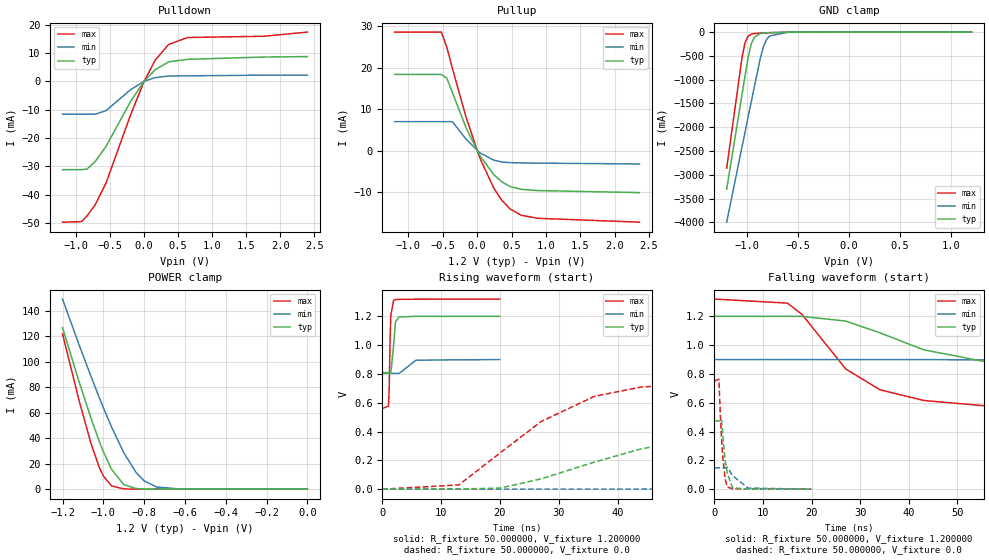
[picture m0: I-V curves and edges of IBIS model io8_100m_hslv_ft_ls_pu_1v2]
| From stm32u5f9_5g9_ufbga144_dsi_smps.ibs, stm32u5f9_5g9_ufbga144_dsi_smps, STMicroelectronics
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|   Model io8_100m_hslv_ft_ls_pu_1v2
[Model]  io8_100m_hslv_ft_ls_pu_1v2
Model_type I/O
Polarity   Non-Inverting
Enable   Active-Low
Vinl =   0.360000V
Vinh =   0.840000V
Vmeas =  0.600000V
Cref =   50.000000pF
Rref =   100.000000M
Vref =   0.0V
C_comp   3.030000pF   2.960800pF   3.078200pF
[Temperature Range]   25.000000   0.140000k   -40.000000
[Pullup Reference]   1.200000V   0.900000V   1.320000V
[Pulldown Reference]   0.0V   0.0V   0.0V
[POWER Clamp Reference]   1.200000V   0.900000V   1.320000V
[GND Clamp Reference]   0.0V   0.0V   0.0V
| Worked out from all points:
|   slope of the pulldown table from 0 to 0.18 V, typ, clamps not added: 40.7 ohm
|   slope of the pullup table from 0 to 0.18 V, typ, clamps not added: 39.5 ohm
|   GND clamp passes 1 mA (typ) near -0.51 V on its own axis
|   POWER clamp passes 1 mA (typ) near -0.86 V on its own axis
|   rising waveform, R_fixture 50.000000, V_fixture 1.200000: 20-80 % time 345ps typ, 818ps min, 225ps max; typ from 0.809 V to 1.2 V
|   rising waveform, R_fixture 50.000000, V_fixture 0.0: 20-80 % time 28.3ns typ, 68.3ns min, 16ns max; typ from 0.001 V to 0.474 V
|   falling waveform, R_fixture 50.000000, V_fixture 1.200000: 20-80 % time 23.6ns typ, 56.9ns min, 13.4ns max; typ from 1.2 V to 0.809 V
|   falling waveform, R_fixture 50.000000, V_fixture 0.0: 20-80 % time 1.04ns typ, 1.96ns min, 794ps max; typ from 0.474 V to 0.001 V
[Pulldown]
|Voltage   I(typ)   I(min)   I(max)
-1.2V     -31.16mA   -11.61mA   -49.71mA
-920mV    -31.16mA   -11.61mA   -49.49mA
-840mV    -31mA      -11.61mA   -47.54mA
-720mV    -28.32mA   -11.61mA   -43.58mA
-560mV    -22.95mA   -10.36mA   -35.89mA
-200mV    -7.146mA   -2.962mA   -11.89mA
0V        0A         0A         0A
160mV     4.047mA    1.297mA    7.361mA
360mV     6.869mA    1.868mA    13mA
640mV     7.764mA    1.921mA    15.46mA
1.76V     8.563mA    2.176mA    15.9mA
2.4V      8.725mA    2.176mA    17.37mA
[Pullup]
|Voltage   I(typ)   I(min)   I(max)
-1.2V     18.39mA    7.011mA    28.61mA
-520mV    18.39mA    7.011mA    28.61mA
-440mV    17.47mA    7.011mA    24.94mA
-360mV    14.06mA    7.011mA    19.88mA
-160mV    5.494mA    2.765mA    8.045mA
40mV      -1.16mA    -507.9uA   -1.774mA
240mV     -5.73mA    -2.255mA   -8.953mA
360mV     -7.518mA   -2.714mA   -11.96mA
480mV     -8.639mA   -2.875mA   -14.04mA
640mV     -9.31mA    -2.939mA   -15.55mA
880mV     -9.601mA   -2.983mA   -16.29mA
2.36V     -10.1mA    -3.2mA     -17.23mA
[GND_clamp]
|Voltage   I(typ)   I(min)   I(max)
-1.2V     -3.305A    -3.998A    -2.862A
-1.05V    -1.316A    -2.418A    -539.3mA
-1.02V    -921mA     -2.103A    -218.8mA
-990mV    -539.5mA   -1.788A    -87.43mA
-960mV    -252.1mA   -1.474A    -44.36mA
-930mV    -110.5mA   -1.16A     -30.32mA
-870mV    -28.03mA   -549.1mA   -21.09mA
-840mV    -18.43mA   -305.6mA   -18.27mA
-810mV    -13.9mA    -159.7mA   -15.73mA
-780mV    -11.23mA   -82.35mA   -13.37mA
-600mV    -2.976mA   -4.272mA   -3.058mA
1.2V      0A         14.73nA    0A
[POWER_clamp]
|Voltage   I(typ)   I(min)   I(max)
-1.2V     127mA      149.4mA    122.2mA
-1.12V    84.98mA    114mA      70.29mA
-1.06V    55.52mA    88.42mA    35.69mA
-1.02V    37.64mA    72.04mA    17.19mA
-1V       29.52mA    64.13mA    10.33mA
-960mV    15.7mA     48.99mA    2.596mA
-900mV    3.636mA    28.77mA    207.8uA
-840mV    502.9uA    13.24mA    43.56uA
-800mV    129uA      6.535mA    43.56uA
-740mV    25.39uA    1.726mA    43.56uA
-620mV    25.22uA    82.33uA    36.06uA
0V        0A         17.33nA    0A
[Ramp]
| variable   typ   min   max
dV/dt_r  0.28386/28.26569n   88.90177m/68.25460n 0.45097/16.01528n
dV/dt_f  0.23429/23.46226n   57.78000m/56.82292n 0.45608/13.31892n
R_load = 50.000000
[Rising Waveform]
R_fixture= 50.000000
V_fixture= 1.200000
V_fixture_min= 0.900000
V_fixture_max= 1.320000
|time   V(typ)   V(min)   V(max)
0s        809.5mV    803.7mV    559.9mV
1.041ns   809.6mV    803.7mV    577.2mV
1.161ns   809.1mV    803.7mV    690.7mV
1.321ns   806.3mV    803.7mV    1.05V
1.441ns   804.1mV    803.7mV    1.209V
1.922ns   1.005V     803.7mV    1.312V
2.242ns   1.163V     803.8mV    1.317V
2.843ns   1.196V     803.5mV    1.318V
5.726ns   1.2V       896mV      1.319V
19.94ns   1.2V       900mV      1.32V
[Rising Waveform]
R_fixture= 50.000000
V_fixture= 0.0
V_fixture_min= 0.0
V_fixture_max= 0.0
|time   V(typ)   V(min)   V(max)
0s        591.7uV    600.4uV    545.2uV
13.01ns   1.408mV    841.7uV    29.79mV
20.02ns   7.847mV    853.3uV    252mV
27.03ns   72.56mV    891.2uV    470.5mV
36.04ns   188.1mV    1.048mV    644.4mV
44.04ns   280.4mV    1.23mV     709.6mV
58.06ns   384.6mV    4.151mV    743.9mV
91.09ns   463mV      46.26mV    751.9mV
193.2ns   473.7mV    140.2mV    752.1mV
498.5ns   473.8mV    148.9mV    752.2mV
[Falling Waveform]
R_fixture= 50.000000
V_fixture= 1.200000
V_fixture_min= 0.900000
V_fixture_max= 1.320000
|time   V(typ)   V(min)   V(max)
0s        1.2V       900mV      1.32V
15.02ns   1.2V       900.2mV    1.292V
18.02ns   1.2V       900.1mV    1.213V
27.03ns   1.167V     900mV      834.7mV
34.03ns   1.086V     900mV      690.9mV
43.04ns   968mV      899.9mV    616.1mV
56.06ns   883.2mV    897.7mV    578.1mV
83.08ns   826mV      868.8mV    562.2mV
166.2ns   809.6mV    812mV      559.9mV
498.5ns   809.5mV    803.7mV    559.9mV
[Falling Waveform]
R_fixture= 50.000000
V_fixture= 0.0
V_fixture_min= 0.0
V_fixture_max= 0.0
|time   V(typ)   V(min)   V(max)
0s        473.8mV    148.9mV    752.2mV
920.9ps   474.2mV    149mV      763.7mV
1.201ns   475.8mV    149mV      525.1mV
1.441ns   485.5mV    149mV      362.5mV
1.682ns   393.1mV    149.1mV    238.6mV
2.202ns   196.8mV    148.9mV    68.8mV
2.643ns   111.3mV    152.7mV    15.72mV
3.724ns   9.728mV    94.41mV    2.95mV
6.927ns   681uV      8.118mV    1.67mV
19.94ns   591.7uV    600.4uV    545.2uV
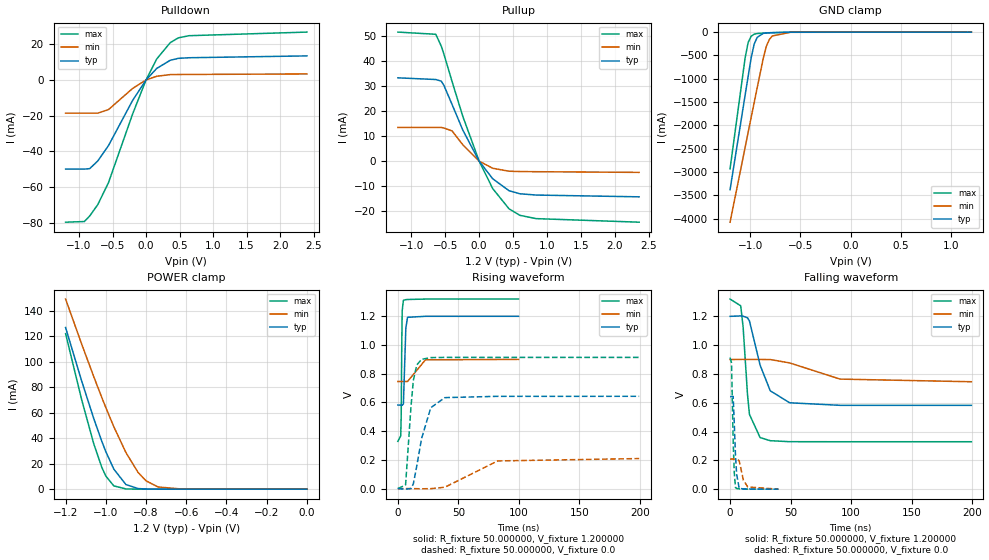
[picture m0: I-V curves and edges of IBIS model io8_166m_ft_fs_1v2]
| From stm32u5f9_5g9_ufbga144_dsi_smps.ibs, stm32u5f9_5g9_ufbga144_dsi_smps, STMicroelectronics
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|   Model io8_166m_ft_fs_1v2
[Model]  io8_166m_ft_fs_1v2
Model_type I/O
Polarity   Non-Inverting
Enable   Active-Low
Vinl =   0.360000V
Vinh =   0.840000V
Vmeas =  0.600000V
Cref =   50.000000pF
Rref =   100.000000M
Vref =   0.0V
C_comp   3.151500pF   3.086800pF   3.197700pF
[Temperature Range]   25.000000   0.140000k   -40.000000
[Pullup Reference]   1.200000V   0.900000V   1.320000V
[Pulldown Reference]   0.0V   0.0V   0.0V
[POWER Clamp Reference]   1.200000V   0.900000V   1.320000V
[GND Clamp Reference]   0.0V   0.0V   0.0V
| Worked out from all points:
|   slope of the pulldown table from 0 to 0.18 V, typ, clamps not added: 25.4 ohm
|   slope of the pullup table from 0 to 0.18 V, typ, clamps not added: 27.8 ohm
|   GND clamp passes 1 mA (typ) near -0.51 V on its own axis
|   POWER clamp passes 1 mA (typ) near -0.86 V on its own axis
|   rising waveform, R_fixture 50.000000, V_fixture 1.200000: 20-80 % time 1.12ns typ, 3.02ns min, 570ps max; typ from 0.582 V to 1.2 V
|   rising waveform, R_fixture 50.000000, V_fixture 0.0: 20-80 % time 9.52ns typ, 24.6ns min, 4.59ns max; typ from 0 V to 0.643 V
|   falling waveform, R_fixture 50.000000, V_fixture 1.200000: 20-80 % time 12ns typ, 29.2ns min, 5.06ns max; typ from 1.2 V to 0.582 V
|   falling waveform, R_fixture 50.000000, V_fixture 0.0: 20-80 % time 1.95ns typ, 3.63ns min, 1.46ns max; typ from 0.643 V to 0 V
[Pulldown]
|Voltage   I(typ)   I(min)   I(max)
-1.2V     -49.86mA   -18.57mA   -79.57mA
-920mV    -49.86mA   -18.57mA   -79.2mA
-840mV    -49.6mA    -18.57mA   -76.08mA
-720mV    -45.32mA   -18.57mA   -69.74mA
-560mV    -36.71mA   -16.58mA   -57.44mA
-200mV    -11.43mA   -4.74mA    -19.03mA
0V        0A         -500fA     0A
160mV     6.477mA    2.075mA    11.78mA
360mV     10.99mA    2.99mA     20.81mA
480mV     12.07mA    3.054mA    23.53mA
640mV     12.43mA    3.075mA    24.76mA
2.4V      13.46mA    3.37mA     26.78mA
[Pullup]
|Voltage   I(typ)   I(min)   I(max)
-1.2V     33.42mA    13.53mA    51.76mA
-640mV    32.74mA    13.53mA    50.88mA
-560mV    32.1mA     13.53mA    46.17mA
-520mV    30.37mA    13.29mA    42.92mA
-400mV    22.74mA    12.14mA    31.93mA
-240mV    12.39mA    6.508mA    17.85mA
0V        580fA      234pA      0A
200mV     -7.072mA   -2.851mA   -11mA
440mV     -11.84mA   -4.03mA    -19.1mA
600mV     -13.07mA   -4.154mA   -21.71mA
840mV     -13.59mA   -4.223mA   -23.04mA
2.36V     -14.3mA    -4.5mA     -24.47mA
[GND_clamp]
|Voltage   I(typ)   I(min)   I(max)
-1.2V     -3.379A    -4.076A    -2.932A
-1.05V    -1.35A     -2.47A     -550.7mA
-1.02V    -947.8mA   -2.149A    -221.5mA
-990mV    -552.4mA   -1.829A    -88.44mA
-960mV    -255.3mA   -1.51A     -44.87mA
-930mV    -111.8mA   -1.191A    -30.68mA
-870mV    -28.36mA   -564.6mA   -21.34mA
-840mV    -18.65mA   -309.5mA   -18.49mA
-810mV    -14.07mA   -161.6mA   -15.92mA
-780mV    -11.37mA   -83.33mA   -13.53mA
-600mV    -3.009mA   -4.322mA   -3.091mA
1.2V      0A         13.65nA    0A
[POWER_clamp]
|Voltage   I(typ)   I(min)   I(max)
-1.2V     127mA      149.4mA    122.2mA
-1.12V    84.97mA    114mA      70.27mA
-1.06V    55.51mA    88.42mA    35.67mA
-1.02V    37.63mA    72.04mA    17.17mA
-1V       29.51mA    64.13mA    10.3mA
-960mV    15.69mA    48.99mA    2.571mA
-900mV    3.624mA    28.77mA    182.8uA
-840mV    490.7uA    13.24mA    11.35uA
-800mV    116.8uA    6.532mA    1.77uA
-740mV    13.2uA     1.724mA    109.1nA
-620mV    167.4nA    79.36uA    0A
0V        0A         17.87nA    0A
[Ramp]
| variable   typ   min   max
dV/dt_r  0.38562/9.51064n   0.12548/24.55913n   0.54826/4.57912n
dV/dt_f  0.37087/11.97332n   92.44800m/29.20183n 0.59438/5.04838n
R_load = 50.000000
[Rising Waveform]
R_fixture= 50.000000
V_fixture= 1.200000
V_fixture_min= 0.900000
V_fixture_max= 1.320000
|time   V(typ)   V(min)   V(max)
0s        581.9mV    745.9mV    329.4mV
2.402ns   582mV      745.9mV    367.6mV
2.803ns   582mV      745.9mV    517.9mV
3.203ns   581.5mV    745.9mV    965.7mV
3.604ns   580.2mV    745.9mV    1.239V
4.605ns   589mV      745.9mV    1.311V
6.607ns   1.116V     745.9mV    1.316V
8.008ns   1.193V     745.9mV    1.317V
22.82ns   1.2V       896.8mV    1.32V
99.7ns    1.2V       900mV      1.32V
[Rising Waveform]
R_fixture= 50.000000
V_fixture= 0.0
V_fixture_min= 0.0
V_fixture_max= 0.0
|time   V(typ)   V(min)   V(max)
0s        1.413uV    1.121uV    1.253uV
6.406ns   -3.831mV   413nV      25.35mV
10.81ns   771.6uV    3.329uV    563.2mV
12.81ns   32.74mV    37.8uV     752.9mV
15.62ns   155.8mV    -550.3uV   860.7mV
19.62ns   348.5mV    -1.365mV   900.4mV
27.23ns   563.5mV    -221.4uV   912.3mV
38.84ns   633.6mV    9.681mV    913.7mV
82.48ns   642.7mV    192.8mV    913.7mV
199.4ns   642.8mV    209.3mV    913.8mV
[Falling Waveform]
R_fixture= 50.000000
V_fixture= 1.200000
V_fixture_min= 0.900000
V_fixture_max= 1.320000
|time   V(typ)   V(min)   V(max)
0s        1.2V       900mV      1.32V
8.809ns   1.203V     901.1mV    1.273V
10.81ns   1.201V     901.2mV    1.124V
14.41ns   1.19V      900.6mV    657.4mV
16.02ns   1.168V     900.6mV    519.4mV
24.82ns   861.1mV    900.6mV    358.2mV
33.23ns   682.9mV    900mV      336.5mV
49.25ns   599.8mV    876.6mV    329.7mV
90.89ns   582.2mV    764.2mV    329.4mV
199.4ns   581.9mV    745.9mV    329.4mV
[Falling Waveform]
R_fixture= 50.000000
V_fixture= 0.0
V_fixture_min= 0.0
V_fixture_max= 0.0
|time   V(typ)   V(min)   V(max)
0s        642.8mV    209.3mV    913.8mV
1.201ns   642.6mV    209.3mV    877.2mV
2.563ns   644mV      209.3mV    333mV
3.443ns   466.1mV    209.2mV    120.2mV
4.484ns   234.5mV    208.9mV    11.92mV
5.445ns   103.8mV    210.9mV    4.661mV
7.528ns   6.591mV    197.8mV    2.295mV
11.05ns   1.415mV    61.13mV    857.5uV
14.65ns   736.8uV    15.42mV    353.8uV
39.88ns   1.413uV    1.121uV    1.253uV
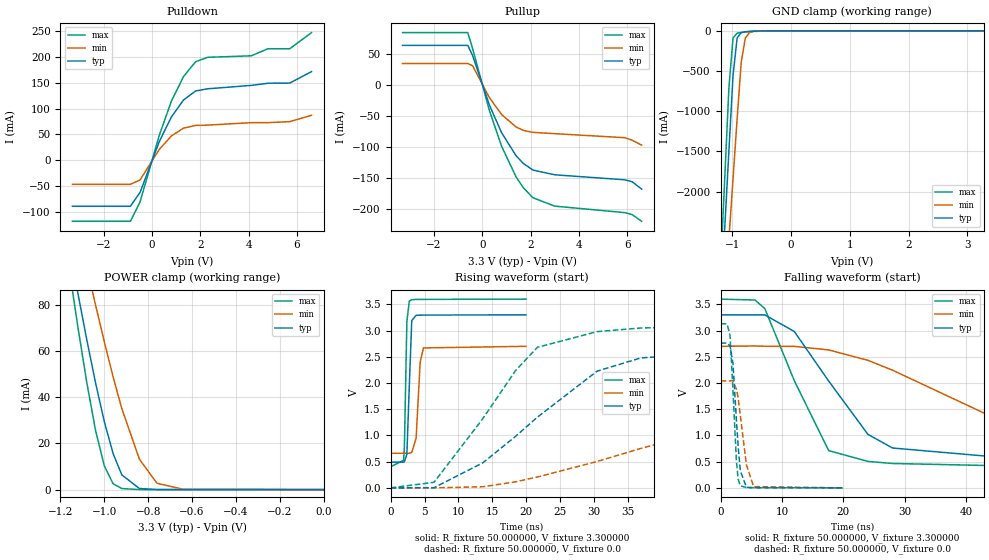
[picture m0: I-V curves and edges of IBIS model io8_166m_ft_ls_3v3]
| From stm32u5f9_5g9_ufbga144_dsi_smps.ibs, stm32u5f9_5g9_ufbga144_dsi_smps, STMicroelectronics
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|   Model io8_166m_ft_ls_3v3
[Model]  io8_166m_ft_ls_3v3
Model_type I/O
Polarity   Non-Inverting
Enable   Active-Low
Vinl =   0.990000V
Vinh =   2.310000V
Vmeas =  1.650000V
Cref =   50.000000pF
Rref =   100.000000M
Vref =   0.0V
C_comp   3.517100pF   3.489300pF   3.557700pF
[Temperature Range]   25.000000   0.140000k   -40.000000
[Pullup Reference]   3.300000V   2.700000V   3.600000V
[Pulldown Reference]   0.0V   0.0V   0.0V
[POWER Clamp Reference]   3.300000V   2.700000V   3.600000V
[GND Clamp Reference]   0.0V   0.0V   0.0V
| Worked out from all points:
|   slope of the pulldown table from 0 to 0.495 V, typ, clamps not added: 8.73 ohm
|   slope of the pullup table from 0 to 0.495 V, typ, clamps not added: 9.64 ohm
|   GND clamp passes 1 mA (typ) near -0.50 V on its own axis
|   POWER clamp passes 1 mA (typ) near -0.85 V on its own axis
|   rising waveform, R_fixture 50.000000, V_fixture 3.300000: 20-80 % time 307ps typ, 455ps min, 272ps max; typ from 0.49 V to 3.3 V
|   rising waveform, R_fixture 50.000000, V_fixture 0.0: 20-80 % time 15.8ns typ, 34.2ns min, 10.3ns max; typ from 0 V to 2.76 V
|   falling waveform, R_fixture 50.000000, V_fixture 3.300000: 20-80 % time 10.1ns typ, 22.3ns min, 6.59ns max; typ from 3.3 V to 0.49 V
|   falling waveform, R_fixture 50.000000, V_fixture 0.0: 20-80 % time 898ps typ, 1.3ns min, 736ps max; typ from 2.76 V to 0 V
[Pulldown]
|Voltage   I(typ)   I(min)   I(max)
-3.3V     -89.72mA   -47.06mA   -119mA
-900mV    -89.72mA   -47.06mA   -119mA
-500mV    -62.92mA   -38.71mA   -81.44mA
300mV     36.2mA     21.01mA    48.7mA
800mV     84.07mA    46.96mA    114.8mA
1.3V      116.7mA    62.09mA    162.4mA
1.8V      134.4mA    67.39mA    191.2mA
2.3V      138.6mA    67.98mA    199.8mA
4.1V      145.2mA    72.79mA    202.7mA
4.8V      149.4mA    72.79mA    216.5mA
5.7V      149.8mA    74.8mA     216.5mA
6.6V      172mA      87.1mA     247.9mA
[Pullup]
|Voltage   I(typ)   I(min)   I(max)
-3.3V     64.11mA    34.77mA    84.74mA
-600mV    64.11mA    34.77mA    84.74mA
-400mV    47.78mA    31.25mA    59.06mA
300mV     -32.62mA   -20.62mA   -41.63mA
800mV     -76.87mA   -47.45mA   -98.74mA
1.4V      -114.1mA   -67.68mA   -148.3mA
1.7V      -126.6mA   -73.14mA   -165.8mA
2.1V      -137.3mA   -76.42mA   -182mA
3V        -144.9mA   -78.48mA   -195.5mA
5.9V      -153mA     -85mA      -206mA
6.2V      -156mA     -89mA      -209mA
6.6V      -168mA     -97mA      -220mA
[GND_clamp]
|Voltage   I(typ)   I(min)   I(max)
-3.3V     -9.098A    -9.372A    -9.671A
-1.2V     -3.386A    -4.091A    -2.933A
-1.13V    -2.437A    -3.34A     -1.815A
-1.06V    -1.49A     -2.588A    -705.6mA
-990mV    -555.7mA   -1.839A    -89.03mA
-920mV    -88.12mA   -1.093A    -28.78mA
-850mV    -22.35mA   -387.4mA   -19.84mA
-780mV    -12.12mA   -88.01mA   -13.88mA
-710mV    -7.71mA    -22.52mA   -8.846mA
-640mV    -4.545mA   -7.864mA   -4.87mA
-360mV    -31.12uA   -173.5uA   -8.497uA
3.28V     0A         14.15nA    -7.901nA
[POWER_clamp]
|Voltage   I(typ)   I(min)   I(max)
-3.28V    1.355A     1.167A     1.664A
-1.16V    105.7mA    131.6mA    95.69mA
-1.12V    84.97mA    114mA      70.27mA
-1.08V    65.05mA    96.83mA    46.54mA
-1.04V    46.34mA    80.15mA    25.76mA
-1V       29.51mA    64.13mA    10.3mA
-960mV    15.69mA    48.99mA    2.571mA
-920mV    6.373mA    35.1mA     455.6uA
-840mV    490.7uA    13.24mA    11.36uA
-760mV    27.33uA    2.767mA    278.2nA
-640mV    347.6nA    134.1uA    16.76nA
0V        0A         19.95nA    0A
[Ramp]
| variable   typ   min   max
dV/dt_r  1.65714/15.82096n   1.22460/34.18746n   1.87854/10.26230n
dV/dt_f  1.68607/10.06722n   1.22416/22.25695n   1.91789/6.56747n
R_load = 50.000000
[Rising Waveform]
R_fixture= 50.000000
V_fixture= 3.300000
V_fixture_min= 2.700000
V_fixture_max= 3.600000
|time   V(typ)   V(min)   V(max)
0s        489.9mV    659.7mV    403.5mV
1.922ns   489.6mV    659.8mV    523.8mV
2.042ns   498.4mV    659.7mV    806.5mV
2.402ns   639.9mV    659.5mV    3.176V
2.763ns   1.96V      658.5mV    3.563V
3.123ns   3.191V     676.4mV    3.589V
3.764ns   3.291V     947mV      3.594V
4.364ns   3.295V     2.401V     3.595V
4.845ns   3.296V     2.669V     3.595V
19.94ns   3.3V       2.7V       3.6V
[Rising Waveform]
R_fixture= 50.000000
V_fixture= 0.0
V_fixture_min= 0.0
V_fixture_max= 0.0
|time   V(typ)   V(min)   V(max)
0s        15.77nV    114.3nV    49.88nV
6.406ns   3.475mV    -605.6uV   105.5mV
13.61ns   478.2mV    20.16mV    1.323V
18.42ns   982.1mV    115.1mV    2.237V
21.62ns   1.347V     206.1mV    2.68V
30.43ns   2.226V     502.6mV    2.98V
36.84ns   2.477V     750.7mV    3.049V
62.46ns   2.711V     1.641V     3.121V
90.49ns   2.752V     1.918V     3.13V
398.8ns   2.762V     2.041V     3.131V
[Falling Waveform]
R_fixture= 50.000000
V_fixture= 3.300000
V_fixture_min= 2.700000
V_fixture_max= 3.600000
|time   V(typ)   V(min)   V(max)
0s        3.3V       2.7V       3.6V
5.606ns   3.3V       2.707V     3.583V
7.207ns   3.299V     2.701V     3.418V
12.01ns   2.982V     2.699V     2.044V
17.62ns   2.037V     2.631V     710.3mV
24.02ns   1.021V     2.433V     504.4mV
28.03ns   760.3mV    2.245V     465mV
49.65ns   541.1mV    1.06V      411.1mV
79.28ns   499.8mV    764.9mV    404.2mV
398.8ns   489.9mV    659.7mV    403.5mV
[Falling Waveform]
R_fixture= 50.000000
V_fixture= 0.0
V_fixture_min= 0.0
V_fixture_max= 0.0
|time   V(typ)   V(min)   V(max)
0s        2.762V     2.041V     3.131V
1.041ns   2.762V     2.041V     3.128V
1.522ns   2.707V     2.041V     2.908V
2.002ns   2.377V     2.044V     1.867V
2.563ns   1.296V     1.883V     513.1mV
2.843ns   797.4mV    1.716V     168.8mV
3.203ns   324.2mV    1.382V     40.82mV
4.204ns   10.79mV    438mV      4.738mV
5.365ns   2.577mV    24.42mV    3.023mV
19.94ns   15.77nV    114.3nV    49.88nV
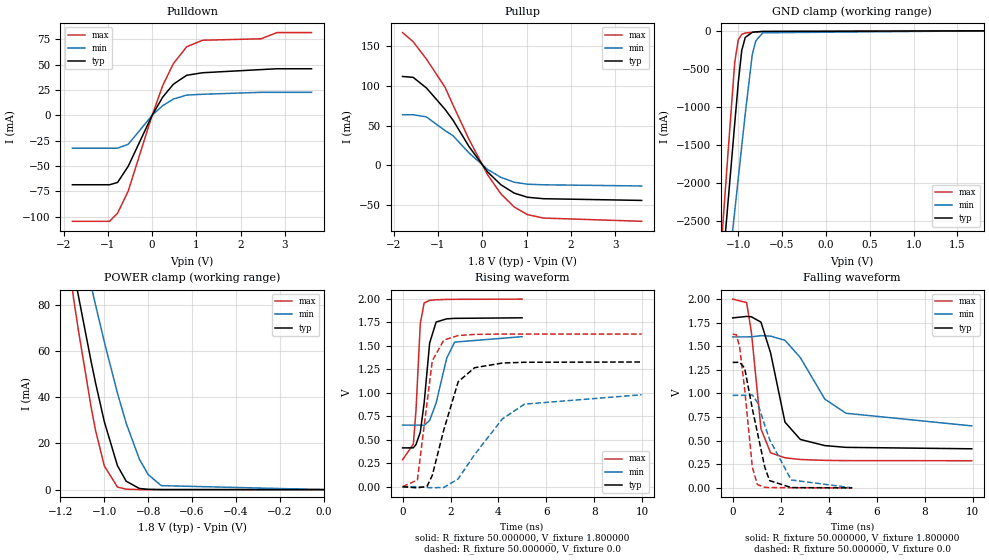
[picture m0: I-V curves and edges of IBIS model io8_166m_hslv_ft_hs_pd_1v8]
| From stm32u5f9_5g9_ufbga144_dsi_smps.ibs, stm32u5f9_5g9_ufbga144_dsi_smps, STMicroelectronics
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|   Model io8_166m_hslv_ft_hs_pd_1v8
[Model]  io8_166m_hslv_ft_hs_pd_1v8
Model_type I/O
Polarity   Non-Inverting
Enable   Active-Low
Vinl =   0.540000V
Vinh =   1.260000V
Vmeas =  0.900000V
Cref =   50.000000pF
Rref =   100.000000M
Vref =   0.0V
C_comp   3.358400pF   3.352800pF   3.400400pF
[Temperature Range]   25.000000   0.140000k   -40.000000
[Pullup Reference]   1.800000V   1.600000V   2.000000V
[Pulldown Reference]   0.0V   0.0V   0.0V
[POWER Clamp Reference]   1.800000V   1.600000V   2.000000V
[GND Clamp Reference]   0.0V   0.0V   0.0V
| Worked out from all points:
|   slope of the pulldown table from 0 to 0.27 V, typ, clamps not added: 13.6 ohm
|   slope of the pullup table from 0 to 0.27 V, typ, clamps not added: 15.9 ohm
|   GND clamp passes 1 mA (typ) near -0.50 V on its own axis
|   POWER clamp passes 1 mA (typ) near -0.86 V on its own axis
|   rising waveform, R_fixture 50.000000, V_fixture 1.800000: 20-80 % time 311ps typ, 546ps min, 203ps max; typ from 0.414 V to 1.8 V
|   rising waveform, R_fixture 50.000000, V_fixture 0.0: 20-80 % time 837ps typ, 1.8ns min, 451ps max; typ from 0 V to 1.33 V
|   falling waveform, R_fixture 50.000000, V_fixture 1.800000: 20-80 % time 688ps typ, 1.56ns min, 401ps max; typ from 1.8 V to 0.414 V
|   falling waveform, R_fixture 50.000000, V_fixture 0.0: 20-80 % time 636ps typ, 924ps min, 385ps max; typ from 1.33 V to 0 V
[Pulldown]
|Voltage   I(typ)   I(min)   I(max)
-1.8V     -68.38mA   -32.32mA   -104.4mA
-960mV    -68.38mA   -32.32mA   -104.4mA
-780mV    -66.08mA   -32.32mA   -96.43mA
-540mV    -50.22mA   -28.51mA   -74.66mA
0V        -10fA      -300fA     0A
240mV     18.04mA    9.6mA      29.42mA
480mV     30.68mA    16.02mA    50.95mA
780mV     39.48mA    19.99mA    67.56mA
1.14V     41.99mA    20.78mA    74.01mA
2.46V     45.09mA    22.7mA     75.45mA
2.82V     45.91mA    22.7mA     81.58mA
3.6V      45.91mA    22.7mA     81.58mA
[Pullup]
|Voltage   I(typ)   I(min)   I(max)
-1.8V     111.9mA    63.74mA    167.2mA
-1.56V    110.8mA    63.74mA    155.7mA
-1.26V    97.43mA    60.93mA    133.8mA
-840mV    70.5mA     43.76mA    98.32mA
-660mV    56.92mA    37.26mA    75.93mA
-300mV    23.77mA    15.64mA    32.82mA
120mV     -8.174mA   -5.123mA   -11.83mA
420mV     -24.43mA   -15.12mA   -35.87mA
720mV     -34.96mA   -21.23mA   -52.43mA
1.02V     -40.21mA   -23.8mA    -62.05mA
1.38V     -42.05mA   -24.52mA   -66.41mA
3.6V      -44.2mA    -26mA      -70.5mA
[GND_clamp]
|Voltage   I(typ)   I(min)   I(max)
-1.8V     -9.908A    -9.683A    -9.994A
-1.2V     -3.383A    -4.084A    -2.934A
-1.16V    -2.841A    -3.655A    -2.294A
-1.12V    -2.299A    -3.226A    -1.656A
-1.04V    -1.218A    -2.369A    -414.2mA
-1V       -684.7mA   -1.941A    -119.2mA
-960mV    -257.2mA   -1.514A    -45.67mA
-920mV    -87.04mA   -1.089A    -28.94mA
-840mV    -19.36mA   -312.8mA   -18.98mA
-800mV    -13.56mA   -132.4mA   -15.51mA
-720mV    -8.053mA   -25.67mA   -9.505mA
1.8V      45.71uA    33.32uA    56.11uA
[POWER_clamp]
|Voltage   I(typ)   I(min)   I(max)
-1.8V     470.8mA    433.7mA    554.6mA
-1.14V    95.25mA    122.7mA    82.82mA
-1.12V    84.97mA    114mA      70.27mA
-1.06V    55.51mA    88.42mA    35.67mA
-1.04V    46.34mA    80.15mA    25.76mA
-1V       29.51mA    64.13mA    10.3mA
-940mV    10.39mA    41.86mA    1.109mA
-900mV    3.624mA    28.77mA    182.8uA
-840mV    490.7uA    13.24mA    11.35uA
-800mV    116.8uA    6.532mA    1.77uA
-740mV    13.2uA     1.724mA    109.3nA
0V        0A         18.75nA    0A
[Ramp]
| variable   typ   min   max
dV/dt_r  0.79734/0.83543n   0.58637/1.79974n   0.97632/0.45044n
dV/dt_f  0.83130/0.68710n   0.56077/1.54034n   1.02744/0.40021n
R_load = 50.000000
[Rising Waveform]
R_fixture= 50.000000
V_fixture= 1.800000
V_fixture_min= 1.600000
V_fixture_max= 2.000000
|time   V(typ)   V(min)   V(max)
0s        413.8mV    656.4mV    287.3mV
450.5ps   414.1mV    656.7mV    453.3mV
560.6ps   448.7mV    656.7mV    810.2mV
740.7ps   581.3mV    655.7mV    1.739V
900.9ps   891.3mV    653.6mV    1.958V
1.131ns   1.532V     706.2mV    1.986V
1.401ns   1.755V     892.9mV    1.992V
1.842ns   1.789V     1.37V      1.996V
2.172ns   1.794V     1.541V     1.997V
4.985ns   1.8V       1.599V     1.999V
[Rising Waveform]
R_fixture= 50.000000
V_fixture= 0.0
V_fixture_min= 0.0
V_fixture_max= 0.0
|time   V(typ)   V(min)   V(max)
0s        -42.81uV   -10.24uV   126.9uV
620.6ps   -12.27mV   149.3uV    71.24mV
1.021ns   2.972mV    -9.352mV   892.1mV
1.241ns   121.5mV    -10.7mV    1.342V
1.722ns   607.1mV    -8.686mV   1.563V
2.322ns   1.119V     84.39mV    1.611V
3.003ns   1.268V     341.6mV    1.623V
4.164ns   1.318V     722.6mV    1.627V
5.085ns   1.326V     880mV      1.627V
9.97ns    1.329V     979.8mV    1.627V
[Falling Waveform]
R_fixture= 50.000000
V_fixture= 1.800000
V_fixture_min= 1.600000
V_fixture_max= 2.000000
|time   V(typ)   V(min)   V(max)
0s        1.8V       1.599V     1.999V
580.6ps   1.816V     1.599V     1.963V
780.8ps   1.812V     1.6V       1.65V
1.181ns   1.755V     1.612V     624.4mV
1.582ns   1.429V     1.607V     371.6mV
2.182ns   695.9mV    1.563V     318.3mV
2.823ns   512.5mV    1.379V     300.4mV
3.844ns   447.6mV    939.7mV    291mV
4.725ns   428.9mV    790.1mV    288.5mV
9.97ns    413.8mV    656.4mV    287.3mV
[Falling Waveform]
R_fixture= 50.000000
V_fixture= 0.0
V_fixture_min= 0.0
V_fixture_max= 0.0
|time   V(typ)   V(min)   V(max)
0s        1.329V     979.8mV    1.627V
150.2ps   1.329V     979.8mV    1.622V
290.3ps   1.331V     979.9mV    1.495V
500.5ps   1.268V     979.8mV    1.045V
820.8ps   837.8mV    983.8mV    218.9mV
1.031ns   587.1mV    906.4mV    35.25mV
1.341ns   216.5mV    660.7mV    5.042mV
1.542ns   76.45mV    510.4mV    3.406mV
2.442ns   2.849mV    83.86mV    968.4uV
4.985ns   -42.81uV   -10.24uV   126.9uV
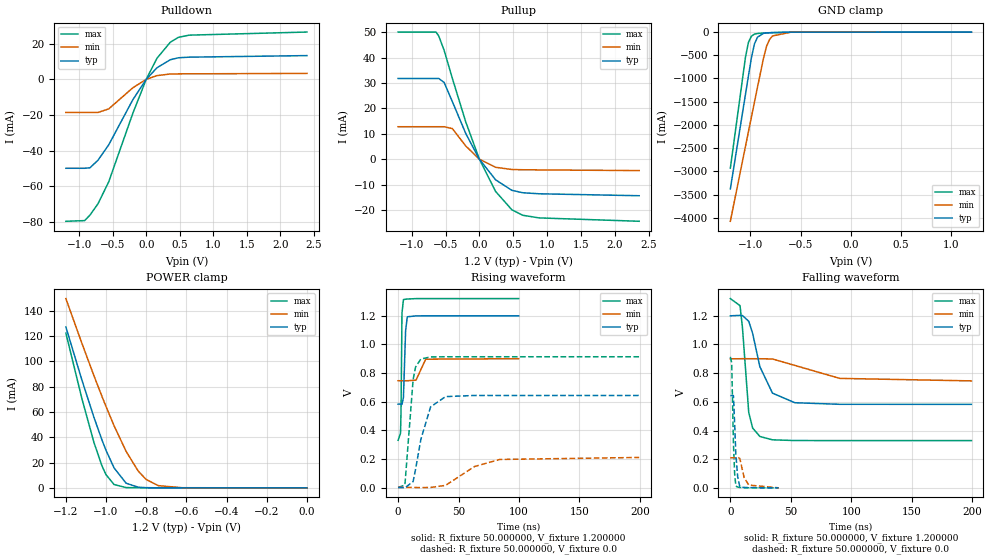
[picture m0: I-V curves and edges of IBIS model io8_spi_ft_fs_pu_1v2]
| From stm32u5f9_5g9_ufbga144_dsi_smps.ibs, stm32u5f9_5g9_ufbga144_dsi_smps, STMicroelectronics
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|   Model io8_spi_ft_fs_pu_1v2
[Model]  io8_spi_ft_fs_pu_1v2
Model_type I/O
Polarity   Non-Inverting
Enable   Active-Low
Vinl =   0.360000V
Vinh =   0.840000V
Vmeas =  0.600000V
Cref =   50.000000pF
Rref =   100.000000M
Vref =   0.0V
C_comp   3.132800pF   3.069700pF   3.178000pF
[Temperature Range]   25.000000   0.140000k   -40.000000
[Pullup Reference]   1.200000V   0.900000V   1.320000V
[Pulldown Reference]   0.0V   0.0V   0.0V
[POWER Clamp Reference]   1.200000V   0.900000V   1.320000V
[GND Clamp Reference]   0.0V   0.0V   0.0V
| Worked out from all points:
|   slope of the pulldown table from 0 to 0.18 V, typ, clamps not added: 25.4 ohm
|   slope of the pullup table from 0 to 0.18 V, typ, clamps not added: 27.8 ohm
|   GND clamp passes 1 mA (typ) near -0.51 V on its own axis
|   POWER clamp passes 1 mA (typ) near -0.86 V on its own axis
|   rising waveform, R_fixture 50.000000, V_fixture 1.200000: 20-80 % time 1.28ns typ, 3.41ns min, 627ps max; typ from 0.583 V to 1.2 V
|   rising waveform, R_fixture 50.000000, V_fixture 0.0: 20-80 % time 9.76ns typ, 25ns min, 4.73ns max; typ from 0 V to 0.643 V
|   falling waveform, R_fixture 50.000000, V_fixture 1.200000: 20-80 % time 12.3ns typ, 30.3ns min, 5.2ns max; typ from 1.2 V to 0.583 V
|   falling waveform, R_fixture 50.000000, V_fixture 0.0: 20-80 % time 2.16ns typ, 4.11ns min, 1.55ns max; typ from 0.643 V to 0 V
[Pulldown]
|Voltage   I(typ)   I(min)   I(max)
-1.2V     -49.85mA   -18.57mA   -79.56mA
-920mV    -49.85mA   -18.57mA   -79.19mA
-840mV    -49.59mA   -18.57mA   -76.08mA
-720mV    -45.32mA   -18.57mA   -69.73mA
-560mV    -36.71mA   -16.58mA   -57.44mA
-200mV    -11.43mA   -4.74mA    -19.03mA
0V        0A         0A         0A
160mV     6.476mA    2.075mA    11.78mA
360mV     10.99mA    2.989mA    20.81mA
480mV     12.07mA    3.053mA    23.52mA
640mV     12.42mA    3.074mA    24.76mA
2.4V      13.3mA     3.331mA    26.5mA
[Pullup]
|Voltage   I(typ)   I(min)   I(max)
-1.2V     31.78mA    12.77mA    50.06mA
-640mV    31.78mA    12.77mA    50.06mA
-600mV    31.78mA    12.77mA    48.51mA
-520mV    30.2mA     12.77mA    42.84mA
-400mV    22.73mA    12.06mA    31.92mA
-200mV    10.05mA    5.174mA    14.59mA
0V        580fA      233pA      0A
240mV     -8.14mA    -3.2mA     -12.72mA
480mV     -12.27mA   -4.078mA   -19.94mA
640mV     -13.22mA   -4.169mA   -22.09mA
880mV     -13.63mA   -4.232mA   -23.13mA
2.36V     -14.4mA    -4.5mA     -24.46mA
[GND_clamp]
|Voltage   I(typ)   I(min)   I(max)
-1.2V     -3.379A    -4.076A    -2.932A
-1.05V    -1.35A     -2.47A     -550.7mA
-1.02V    -947.8mA   -2.149A    -221.5mA
-990mV    -552.4mA   -1.829A    -88.44mA
-960mV    -255.3mA   -1.51A     -44.87mA
-930mV    -111.8mA   -1.191A    -30.68mA
-870mV    -28.35mA   -564.6mA   -21.34mA
-840mV    -18.65mA   -309.5mA   -18.49mA
-810mV    -14.07mA   -161.6mA   -15.92mA
-780mV    -11.37mA   -83.33mA   -13.53mA
-600mV    -3.009mA   -4.321mA   -3.091mA
1.2V      0A         13.65nA    0A
[POWER_clamp]
|Voltage   I(typ)   I(min)   I(max)
-1.2V     127mA      149.4mA    122.2mA
-1.12V    84.98mA    114mA      70.29mA
-1.06V    55.52mA    88.42mA    35.69mA
-1.02V    37.64mA    72.04mA    17.19mA
-1V       29.52mA    64.13mA    10.33mA
-960mV    15.7mA     48.99mA    2.596mA
-900mV    3.636mA    28.77mA    207.8uA
-840mV    502.9uA    13.24mA    43.56uA
-800mV    129uA      6.535mA    43.56uA
-740mV    25.5uA     1.726mA    43.56uA
-620mV    25.17uA    82.33uA    36.07uA
0V        0A         17.36nA    0A
[Ramp]
| variable   typ   min   max
dV/dt_r  0.38567/9.74994n   0.12562/24.94060n   0.54819/4.72269n
dV/dt_f  0.37036/12.27881n   92.32200m/30.34052n 0.59403/5.19564n
R_load = 50.000000
[Rising Waveform]
R_fixture= 50.000000
V_fixture= 1.200000
V_fixture_min= 0.900000
V_fixture_max= 1.320000
|time   V(typ)   V(min)   V(max)
0s        582.7mV    746.1mV    330mV
2.002ns   582.8mV    746.1mV    380.1mV
2.402ns   582.7mV    746.1mV    528.4mV
3.203ns   580.5mV    746.1mV    1.218V
4.404ns   629.2mV    746.1mV    1.313V
6.206ns   1.097V     746.1mV    1.316V
7.608ns   1.193V     746.1mV    1.317V
14.81ns   1.199V     750.3mV    1.32V
22.82ns   1.2V       896.8mV    1.32V
99.7ns    1.2V       900mV      1.32V
[Rising Waveform]
R_fixture= 50.000000
V_fixture= 0.0
V_fixture_min= 0.0
V_fixture_max= 0.0
|time   V(typ)   V(min)   V(max)
0s        435.5uV    496.6uV    378.9uV
5.606ns   -2.176mV   496.2uV    17.05mV
12.41ns   41.79mV    537.6uV    753.7mV
14.41ns   126.1mV    159.5uV    840.9mV
18.82ns   336.1mV    -528.3uV   898.2mV
26.83ns   562.9mV    483.3uV    912.4mV
39.24ns   635.2mV    15mV       913.6mV
63.26ns   643.3mV    147mV      913.7mV
84.08ns   643.2mV    196.1mV    913.7mV
199.4ns   643.3mV    210mV      913.7mV
[Falling Waveform]
R_fixture= 50.000000
V_fixture= 1.200000
V_fixture_min= 0.900000
V_fixture_max= 1.320000
|time   V(typ)   V(min)   V(max)
0s        1.2V       900mV      1.32V
8.008ns   1.203V     900.6mV    1.271V
10.01ns   1.202V     901.1mV    1.119V
15.22ns   1.162V     900.6mV    526.1mV
18.42ns   1.078V     900.7mV    417.8mV
24.42ns   845.4mV    900.6mV    358.5mV
34.83ns   661mV      899mV      335.2mV
53.25ns   594mV      854.3mV    330.2mV
90.49ns   582.9mV    763.7mV    330mV
199.4ns   582.7mV    746.1mV    330mV
[Falling Waveform]
R_fixture= 50.000000
V_fixture= 0.0
V_fixture_min= 0.0
V_fixture_max= 0.0
|time   V(typ)   V(min)   V(max)
0s        643.3mV    210mV      913.7mV
1.121ns   642.8mV    210mV      871.9mV
2.563ns   643.5mV    210mV      306.6mV
3.604ns   438mV      209.8mV    91.63mV
4.565ns   230.6mV    209.8mV    12.39mV
6.086ns   76.18mV    214.6mV    5.45mV
7.848ns   7.858mV    204.8mV    3.138mV
11.45ns   2.905mV    70.31mV    1.332mV
15.3ns    1.803mV    19.44mV    757.5uV
39.88ns   435.5uV    496.6uV    378.9uV
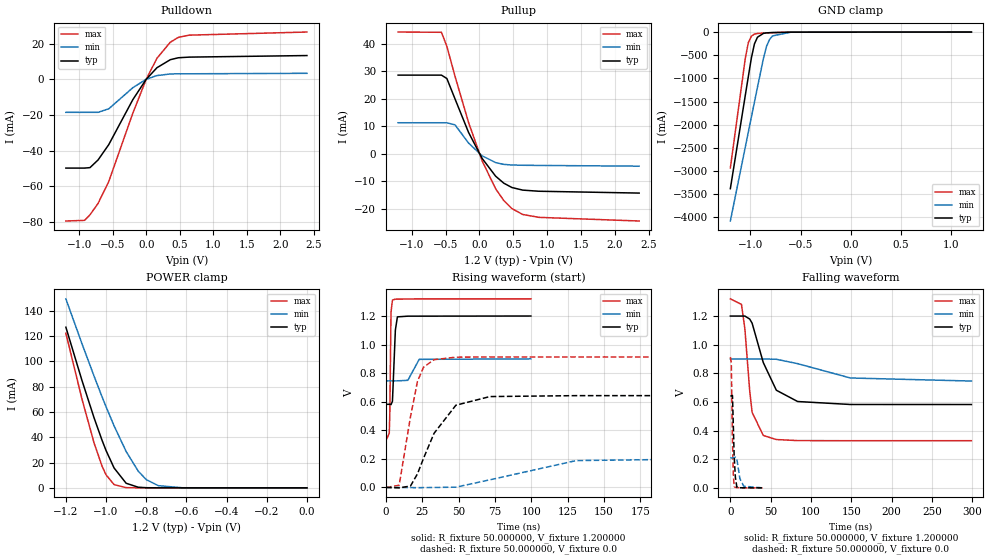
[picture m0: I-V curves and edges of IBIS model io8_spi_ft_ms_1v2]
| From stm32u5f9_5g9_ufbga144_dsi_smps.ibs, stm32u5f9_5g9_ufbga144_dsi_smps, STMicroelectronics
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|   Model io8_spi_ft_ms_1v2
[Model]  io8_spi_ft_ms_1v2
Model_type I/O
Polarity   Non-Inverting
Enable   Active-Low
Vinl =   0.360000V
Vinh =   0.840000V
Vmeas =  0.600000V
Cref =   50.000000pF
Rref =   100.000000M
Vref =   0.0V
C_comp   3.132800pF   3.069700pF   3.178000pF
[Temperature Range]   25.000000   0.140000k   -40.000000
[Pullup Reference]   1.200000V   0.900000V   1.320000V
[Pulldown Reference]   0.0V   0.0V   0.0V
[POWER Clamp Reference]   1.200000V   0.900000V   1.320000V
[GND Clamp Reference]   0.0V   0.0V   0.0V
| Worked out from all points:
|   slope of the pulldown table from 0 to 0.18 V, typ, clamps not added: 25.4 ohm
|   slope of the pullup table from 0 to 0.18 V, typ, clamps not added: 27.8 ohm
|   GND clamp passes 1 mA (typ) near -0.51 V on its own axis
|   POWER clamp passes 1 mA (typ) near -0.86 V on its own axis
|   rising waveform, R_fixture 50.000000, V_fixture 1.200000: 20-80 % time 1.26ns typ, 3.37ns min, 606ps max; typ from 0.582 V to 1.2 V
|   rising waveform, R_fixture 50.000000, V_fixture 0.0: 20-80 % time 18.4ns typ, 45.5ns min, 9.08ns max; typ from 0 V to 0.643 V
|   falling waveform, R_fixture 50.000000, V_fixture 1.200000: 20-80 % time 21.9ns typ, 54.5ns min, 9.2ns max; typ from 1.2 V to 0.582 V
|   falling waveform, R_fixture 50.000000, V_fixture 0.0: 20-80 % time 2.2ns typ, 4.21ns min, 1.58ns max; typ from 0.643 V to 0 V
[Pulldown]
|Voltage   I(typ)   I(min)   I(max)
-1.2V     -49.85mA   -18.57mA   -79.56mA
-920mV    -49.85mA   -18.57mA   -79.19mA
-840mV    -49.59mA   -18.57mA   -76.08mA
-720mV    -45.32mA   -18.57mA   -69.74mA
-560mV    -36.71mA   -16.58mA   -57.44mA
-200mV    -11.43mA   -4.74mA    -19.03mA
0V        0A         -600fA     0A
160mV     6.476mA    2.075mA    11.78mA
360mV     10.99mA    2.989mA    20.81mA
480mV     12.07mA    3.053mA    23.52mA
640mV     12.43mA    3.074mA    24.76mA
2.4V      13.31mA    3.34mA     26.51mA
[Pullup]
|Voltage   I(typ)   I(min)   I(max)
-1.2V     28.65mA    11.31mA    44.34mA
-560mV    28.65mA    11.31mA    44.25mA
-480mV    27.42mA    11.31mA    39.11mA
-360mV    20.01mA    10.55mA    28.26mA
-160mV    7.809mA    3.931mA    11.44mA
40mV      -1.649mA   -721.3uA   -2.521mA
240mV     -8.14mA    -3.2mA     -12.72mA
360mV     -10.68mA   -3.85mA    -16.99mA
480mV     -12.27mA   -4.078mA   -19.94mA
640mV     -13.22mA   -4.169mA   -22.09mA
880mV     -13.63mA   -4.232mA   -23.14mA
2.36V     -14.3mA    -4.5mA     -24.47mA
[GND_clamp]
|Voltage   I(typ)   I(min)   I(max)
-1.2V     -3.379A    -4.076A    -2.932A
-1.05V    -1.35A     -2.47A     -550.7mA
-1.02V    -947.8mA   -2.149A    -221.5mA
-990mV    -552.4mA   -1.829A    -88.44mA
-960mV    -255.3mA   -1.51A     -44.87mA
-930mV    -111.8mA   -1.191A    -30.68mA
-870mV    -28.35mA   -564.6mA   -21.34mA
-840mV    -18.65mA   -309.5mA   -18.49mA
-810mV    -14.07mA   -161.6mA   -15.92mA
-780mV    -11.37mA   -83.33mA   -13.53mA
-600mV    -3.009mA   -4.321mA   -3.091mA
1.2V      0A         13.65nA    0A
[POWER_clamp]
|Voltage   I(typ)   I(min)   I(max)
-1.2V     127mA      149.4mA    122.2mA
-1.12V    84.97mA    114mA      70.27mA
-1.06V    55.51mA    88.42mA    35.67mA
-1.02V    37.63mA    72.04mA    17.17mA
-1V       29.51mA    64.13mA    10.3mA
-960mV    15.69mA    48.99mA    2.571mA
-900mV    3.624mA    28.77mA    182.8uA
-840mV    490.7uA    13.24mA    11.35uA
-800mV    116.8uA    6.532mA    1.77uA
-740mV    13.2uA     1.724mA    109.1nA
-620mV    167.4nA    79.36uA    0A
0V        0A         17.87nA    0A
[Ramp]
| variable   typ   min   max
dV/dt_r  0.38562/18.35174n   0.12550/45.45185n   0.54825/9.06267n
dV/dt_f  0.37078/21.83491n   92.23200m/54.50850n 0.59437/9.19139n
R_load = 50.000000
[Rising Waveform]
R_fixture= 50.000000
V_fixture= 1.200000
V_fixture_min= 0.900000
V_fixture_max= 1.320000
|time   V(typ)   V(min)   V(max)
0s        582mV      746mV      329.4mV
2.202ns   582.1mV    746mV      379mV
2.603ns   582mV      746mV      524.1mV
3.403ns   579.4mV    746mV      1.225V
4.404ns   603.5mV    746mV      1.312V
6.406ns   1.101V     746mV      1.318V
7.808ns   1.194V     746mV      1.318V
15.02ns   1.199V     750.1mV    1.319V
22.82ns   1.199V     896.7mV    1.32V
99.7ns    1.2V       900mV      1.32V
[Rising Waveform]
R_fixture= 50.000000
V_fixture= 0.0
V_fixture_min= 0.0
V_fixture_max= 0.0
|time   V(typ)   V(min)   V(max)
0s        1.4uV      1.115uV    1.278uV
9.009ns   -2.652mV   -411.4nV   15.29mV
16.82ns   10.1mV     -846.3uV   494.4mV
21.62ns   95.21mV    -1.413mV   742.4mV
25.83ns   204.7mV    -896.3uV   841.9mV
33.03ns   378.8mV    -43.62uV   894.5mV
48.05ns   575.5mV    2.189mV    911.9mV
71.47ns   636.2mV    53.58mV    913.4mV
130.9ns   642.7mV    188.2mV    913.5mV
299.1ns   642.8mV    209.3mV    913.5mV
[Falling Waveform]
R_fixture= 50.000000
V_fixture= 1.200000
V_fixture_min= 0.900000
V_fixture_max= 1.320000
|time   V(typ)   V(min)   V(max)
0s        1.2V       900mV      1.32V
13.81ns   1.2V       900.7mV    1.281V
18.02ns   1.2V       900.6mV    1.111V
24.02ns   1.179V     900.7mV    678mV
27.03ns   1.15V      900.5mV    527.2mV
40.84ns   875.4mV    900mV      366.2mV
57.06ns   681.9mV    898.2mV    337.4mV
83.48ns   603mV      867.5mV    330.1mV
148.9ns   582.3mV    767.4mV    329.4mV
299.1ns   582mV      746mV      329.4mV
[Falling Waveform]
R_fixture= 50.000000
V_fixture= 0.0
V_fixture_min= 0.0
V_fixture_max= 0.0
|time   V(typ)   V(min)   V(max)
0s        642.8mV    209.3mV    913.5mV
1.201ns   642.2mV    209.3mV    873.1mV
2.643ns   644.9mV    209.3mV    314.8mV
3.684ns   439.9mV    209.1mV    96.38mV
4.725ns   222.3mV    209.2mV    9.356mV
6.246ns   73.84mV    214.8mV    2.764mV
8.088ns   5.138mV    200.5mV    1.36mV
11.85ns   891.9uV    63.57mV    994.9uV
16.66ns   369.1uV    11.44mV    553.4uV
39.88ns   1.4uV      1.115uV    1.278uV
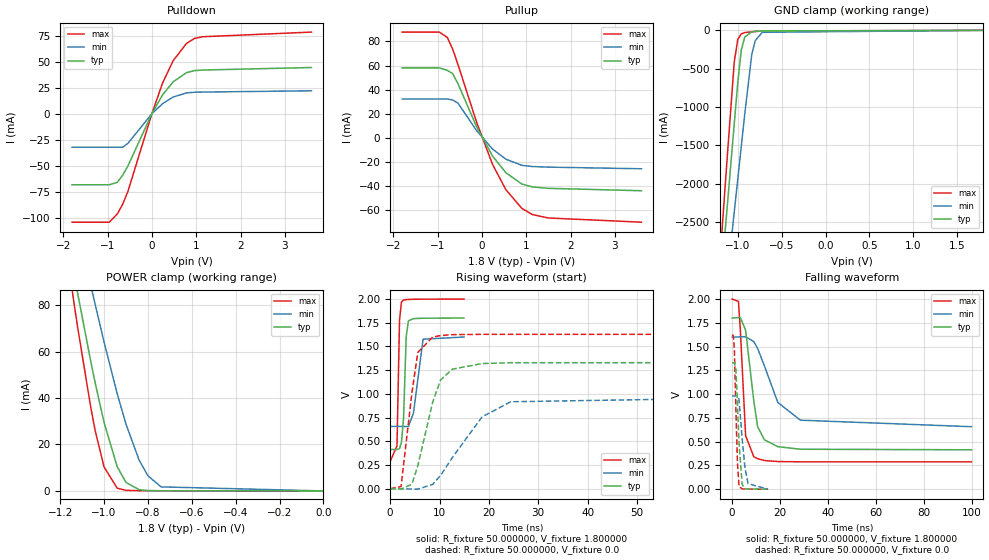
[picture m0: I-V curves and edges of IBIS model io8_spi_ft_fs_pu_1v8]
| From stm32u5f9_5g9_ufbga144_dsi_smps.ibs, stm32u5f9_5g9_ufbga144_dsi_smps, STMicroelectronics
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|   Model io8_spi_ft_fs_pu_1v8
[Model]  io8_spi_ft_fs_pu_1v8
Model_type I/O
Polarity   Non-Inverting
Enable   Active-Low
Vinl =   0.540000V
Vinh =   1.260000V
Vmeas =  0.900000V
Cref =   50.000000pF
Rref =   100.000000M
Vref =   0.0V
C_comp   3.338500pF   3.332300pF   3.378900pF
[Temperature Range]   25.000000   0.140000k   -40.000000
[Pullup Reference]   1.800000V   1.600000V   2.000000V
[Pulldown Reference]   0.0V   0.0V   0.0V
[POWER Clamp Reference]   1.800000V   1.600000V   2.000000V
[GND Clamp Reference]   0.0V   0.0V   0.0V
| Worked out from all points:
|   slope of the pulldown table from 0 to 0.27 V, typ, clamps not added: 13.6 ohm
|   slope of the pullup table from 0 to 0.27 V, typ, clamps not added: 15.9 ohm
|   GND clamp passes 1 mA (typ) near -0.51 V on its own axis
|   POWER clamp passes 1 mA (typ) near -0.86 V on its own axis
|   rising waveform, R_fixture 50.000000, V_fixture 1.800000: 20-80 % time 508ps typ, 1.04ns min, 327ps max; typ from 0.414 V to 1.8 V
|   rising waveform, R_fixture 50.000000, V_fixture 0.0: 20-80 % time 3.77ns typ, 8.23ns min, 1.98ns max; typ from 0 V to 1.33 V
|   falling waveform, R_fixture 50.000000, V_fixture 1.800000: 20-80 % time 3.8ns typ, 9.14ns min, 1.94ns max; typ from 1.8 V to 0.414 V
|   falling waveform, R_fixture 50.000000, V_fixture 0.0: 20-80 % time 1.38ns typ, 2.03ns min, 1ns max; typ from 1.33 V to 0 V
[Pulldown]
|Voltage   I(typ)   I(min)   I(max)
-1.8V     -68.38mA   -32.32mA   -104.4mA
-960mV    -68.38mA   -32.32mA   -104.4mA
-780mV    -66.07mA   -32.32mA   -96.42mA
-660mV    -59.2mA    -32.31mA   -87.22mA
-540mV    -50.22mA   -28.51mA   -74.66mA
0V        0A         0A         0A
240mV     18.04mA    9.599mA    29.41mA
480mV     30.68mA    16.02mA    50.95mA
780mV     39.47mA    19.98mA    67.56mA
960mV     41.44mA    20.62mA    72.37mA
1.14V     41.98mA    20.78mA    74.01mA
3.6V      44.42mA    22.05mA    78.5mA
[Pullup]
|Voltage   I(typ)   I(min)   I(max)
-1.8V     58.03mA    32.11mA    87.83mA
-960mV    58.03mA    32.11mA    87.83mA
-780mV    55.96mA    32.11mA    83.33mA
-660mV    53.21mA    31.27mA    73.64mA
-540mV    44.81mA    28.64mA    60.83mA
-120mV    9.014mA    5.781mA    12.75mA
240mV     -15.38mA   -9.6mA     -22.37mA
540mV     -29.31mA   -18.02mA   -43.36mA
900mV     -38.69mA   -23.13mA   -58.99mA
1.14V     -41.14mA   -24.16mA   -64.17mA
1.5V      -42.31mA   -24.64mA   -67mA
3.6V      -44.3mA    -26mA      -70.5mA
[GND_clamp]
|Voltage   I(typ)   I(min)   I(max)
-1.8V     -9.908A    -9.683A    -9.994A
-1.2V     -3.383A    -4.084A    -2.934A
-1.16V    -2.841A    -3.655A    -2.294A
-1.12V    -2.299A    -3.226A    -1.656A
-1.04V    -1.218A    -2.369A    -414.2mA
-1V       -684.7mA   -1.941A    -119.2mA
-960mV    -257.2mA   -1.514A    -45.66mA
-920mV    -87.03mA   -1.089A    -28.93mA
-840mV    -19.35mA   -312.8mA   -18.96mA
-800mV    -13.55mA   -132.4mA   -15.49mA
-720mV    -8.042mA   -25.66mA   -9.49mA
1.8V      0A         13.64nA    0A
[POWER_clamp]
|Voltage   I(typ)   I(min)   I(max)
-1.8V     470.9mA    433.7mA    554.6mA
-1.14V    95.28mA    122.7mA    82.88mA
-1.12V    85mA       114mA      70.34mA
-1.06V    55.55mA    88.43mA    35.73mA
-1.04V    46.38mA    80.17mA    25.83mA
-1V       29.54mA    64.14mA    10.37mA
-940mV    10.43mA    41.88mA    1.177mA
-900mV    3.66mA     28.79mA    250.5uA
-840mV    527.2uA    13.26mA    95.13uA
-800mV    153.8uA    6.55mA     88.66uA
-740mV    59.96uA    1.741mA    70.47uA
0V        0A         18.18nA    0A
[Ramp]
| variable   typ   min   max
dV/dt_r  0.79756/3.76236n   0.58807/8.22154n   0.97651/1.97417n
dV/dt_f  0.83131/3.79477n   0.56549/9.13374n   1.02742/1.93868n
R_load = 50.000000
[Rising Waveform]
R_fixture= 50.000000
V_fixture= 1.800000
V_fixture_min= 1.600000
V_fixture_max= 2.000000
|time   V(typ)   V(min)   V(max)
0s        414.5mV    657.5mV    287.7mV
1.381ns   413.6mV    657.5mV    453.7mV
1.892ns   423.5mV    657.6mV    1.775V
2.282ns   489.2mV    657.5mV    1.969V
2.703ns   735.8mV    657.3mV    1.99V
3.243ns   1.6V       655.9mV    1.994V
3.694ns   1.77V      656.7mV    1.996V
4.715ns   1.794V     796.5mV    1.998V
6.667ns   1.798V     1.577V     1.999V
14.95ns   1.8V       1.6V       2V
[Rising Waveform]
R_fixture= 50.000000
V_fixture= 0.0
V_fixture_min= 0.0
V_fixture_max= 0.0
|time   V(typ)   V(min)   V(max)
0s        427.1uV    509.8uV    388.5uV
2.202ns   -3.511mV   509.4uV    23mV
4.404ns   48.67mV    -2.703mV   1.012V
5.606ns   244.4mV    -4.134mV   1.438V
8.609ns   913.3mV    46.21mV    1.599V
10.21ns   1.147V     140.5mV    1.616V
12.61ns   1.261V     330.5mV    1.625V
18.62ns   1.32V      757.6mV    1.628V
24.42ns   1.329V     917.3mV    1.628V
99.7ns    1.33V      980.7mV    1.628V
[Falling Waveform]
R_fixture= 50.000000
V_fixture= 1.800000
V_fixture_min= 1.600000
V_fixture_max= 2.000000
|time   V(typ)   V(min)   V(max)
0s        1.8V       1.6V       2V
2.603ns   1.806V     1.601V     1.975V
3.403ns   1.804V     1.604V     1.679V
5.606ns   1.672V     1.603V     562.4mV
9.009ns   927.5mV    1.553V     341.4mV
10.61ns   657mV      1.48V      320.6mV
13.41ns   520.6mV    1.299V     302mV
19.02ns   447.4mV    912.1mV    290.9mV
28.43ns   420.4mV    726mV      288mV
99.7ns    414.5mV    657.5mV    287.7mV
[Falling Waveform]
R_fixture= 50.000000
V_fixture= 0.0
V_fixture_min= 0.0
V_fixture_max= 0.0
|time   V(typ)   V(min)   V(max)
0s        1.33V      980.7mV    1.628V
510.5ps   1.33V      980.7mV    1.611V
930.9ps   1.334V     980.7mV    1.462V
1.562ns   1.255V     980.5mV    830.7mV
2.192ns   909.2mV    986.9mV    280.3mV
2.853ns   481.7mV    946.2mV    28.9mV
4.174ns   49.49mV    524.3mV    2.778mV
5.345ns   6.026mV    225.1mV    1.463mV
6.607ns   2.688mV    58.02mV    1.022mV
14.95ns   427.1uV    509.8uV    388.5uV
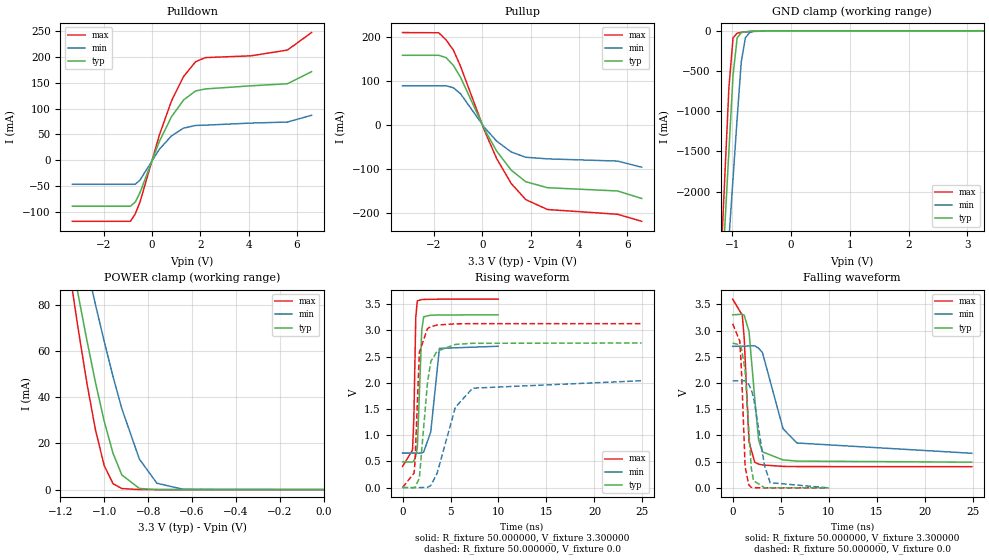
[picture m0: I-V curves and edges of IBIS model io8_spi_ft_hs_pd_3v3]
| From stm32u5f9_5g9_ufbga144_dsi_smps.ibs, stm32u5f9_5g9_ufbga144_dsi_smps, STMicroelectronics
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|   Model io8_spi_ft_hs_pd_3v3
[Model]  io8_spi_ft_hs_pd_3v3
Model_type I/O
Polarity   Non-Inverting
Enable   Active-Low
Vinl =   0.990000V
Vinh =   2.310000V
Vmeas =  1.650000V
Cref =   50.000000pF
Rref =   100.000000M
Vref =   0.0V
C_comp   3.495300pF   3.468500pF   3.534700pF
[Temperature Range]   25.000000   0.140000k   -40.000000
[Pullup Reference]   3.300000V   2.700000V   3.600000V
[Pulldown Reference]   0.0V   0.0V   0.0V
[POWER Clamp Reference]   3.300000V   2.700000V   3.600000V
[GND Clamp Reference]   0.0V   0.0V   0.0V
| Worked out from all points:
|   slope of the pulldown table from 0 to 0.495 V, typ, clamps not added: 8.73 ohm
|   slope of the pullup table from 0 to 0.495 V, typ, clamps not added: 9.64 ohm
|   GND clamp passes 1 mA (typ) near -0.50 V on its own axis
|   POWER clamp passes 1 mA (typ) near -0.85 V on its own axis
|   rising waveform, R_fixture 50.000000, V_fixture 3.300000: 20-80 % time 281ps typ, 498ps min, 209ps max; typ from 0.49 V to 3.3 V
|   rising waveform, R_fixture 50.000000, V_fixture 0.0: 20-80 % time 740ps typ, 2ns min, 395ps max; typ from 0 V to 2.76 V
|   falling waveform, R_fixture 50.000000, V_fixture 3.300000: 20-80 % time 735ps typ, 1.64ns min, 475ps max; typ from 3.3 V to 0.49 V
|   falling waveform, R_fixture 50.000000, V_fixture 0.0: 20-80 % time 556ps typ, 1.05ns min, 388ps max; typ from 2.76 V to 0 V
[Pulldown]
|Voltage   I(typ)   I(min)   I(max)
-3.3V     -89.72mA   -47.06mA   -119mA
-900mV    -89.72mA   -47.06mA   -119mA
-700mV    -81.75mA   -47.06mA   -104.8mA
-500mV    -62.92mA   -38.71mA   -81.44mA
300mV     36.2mA     21.01mA    48.7mA
800mV     84.06mA    46.96mA    114.8mA
1.3V      116.7mA    62.08mA    162.3mA
1.8V      134.4mA    67.38mA    191.2mA
2.2V      138.3mA    67.91mA    199.2mA
4.1V      144.4mA    71.97mA    202.7mA
5.6V      148.4mA    73.93mA    213.9mA
6.6V      171.9mA    87.1mA     247.9mA
[Pullup]
|Voltage   I(typ)   I(min)   I(max)
-3.3V     157.6mA    88.27mA    209.3mA
-1.8V     157.6mA    88.27mA    208.8mA
-1.5V     152.3mA    88.27mA    192.8mA
-1.2V     135.1mA    83.91mA    169.9mA
-900mV    107.7mA    70.22mA    132.8mA
100mV     -11.39mA   -7.258mA   -14.51mA
600mV     -60.65mA   -37.83mA   -77.68mA
1.2V      -103.6mA   -62.35mA   -134mA
1.8V      -129.9mA   -74.33mA   -170.6mA
2.7V      -143.6mA   -78mA      -193.2mA
5.6V      -151mA     -83mA      -204mA
6.6V      -168mA     -97mA      -220mA
[GND_clamp]
|Voltage   I(typ)   I(min)   I(max)
-3.3V     -9.098A    -9.372A    -9.671A
-1.2V     -3.386A    -4.091A    -2.933A
-1.13V    -2.437A    -3.34A     -1.815A
-1.06V    -1.49A     -2.588A    -705.6mA
-990mV    -555.7mA   -1.839A    -89.05mA
-920mV    -88.14mA   -1.093A    -28.79mA
-850mV    -22.36mA   -387.4mA   -19.86mA
-780mV    -12.13mA   -88.01mA   -13.89mA
-710mV    -7.72mA    -22.53mA   -8.86mA
-640mV    -4.556mA   -7.872mA   -4.884mA
-360mV    -39.69uA   -179.8uA   -19.45uA
3.28V     83.52uA    56.87uA    102.4uA
[POWER_clamp]
|Voltage   I(typ)   I(min)   I(max)
-3.28V    1.355A     1.167A     1.664A
-1.16V    105.7mA    131.6mA    95.69mA
-1.12V    84.97mA    114mA      70.27mA
-1.08V    65.05mA    96.83mA    46.54mA
-1.04V    46.34mA    80.15mA    25.76mA
-1V       29.51mA    64.13mA    10.3mA
-960mV    15.69mA    48.99mA    2.571mA
-920mV    6.373mA    35.1mA     455.6uA
-840mV    490.7uA    13.24mA    11.36uA
-760mV    27.33uA    2.767mA    279.3nA
-640mV    348nA      134.1uA    17.47nA
0V        0A         19.95nA    0A
[Ramp]
| variable   typ   min   max
dV/dt_r  1.65672/0.73853n   1.22418/1.99483n   1.87812/0.39236n
dV/dt_f  1.68575/0.73187n   1.22312/1.64274n   1.91751/0.47303n
R_load = 50.000000
[Rising Waveform]
R_fixture= 50.000000
V_fixture= 3.300000
V_fixture_min= 2.700000
V_fixture_max= 3.600000
|time   V(typ)   V(min)   V(max)
0s        489.8mV    659.6mV    403.5mV
1.041ns   487.8mV    659.6mV    715mV
1.181ns   508.5mV    659.6mV    1.327V
1.381ns   601.4mV    659.5mV    3.256V
1.542ns   761.2mV    659.1mV    3.566V
2.002ns   3.001V     659.9mV    3.591V
2.202ns   3.262V     676.7mV    3.593V
2.943ns   3.293V     1.064V     3.596V
3.844ns   3.296V     2.658V     3.598V
9.97ns    3.299V     2.699V     3.599V
[Rising Waveform]
R_fixture= 50.000000
V_fixture= 0.0
V_fixture_min= 0.0
V_fixture_max= 0.0
|time   V(typ)   V(min)   V(max)
0s        3.013uV    4.629uV    8.802uV
1.201ns   -6.177mV   50.46uV    276.8mV
1.301ns   4.902mV    76.26uV    489.8mV
1.752ns   177.9mV    -814.8uV   2.582V
2.603ns   2.012V     2.238mV    3.037V
2.953ns   2.411V     39.08mV    3.072V
3.604ns   2.603V     272.7mV    3.104V
5.506ns   2.734V     1.533V     3.127V
7.307ns   2.755V     1.898V     3.13V
24.92ns   2.761V     2.04V      3.13V
[Falling Waveform]
R_fixture= 50.000000
V_fixture= 3.300000
V_fixture_min= 2.700000
V_fixture_max= 3.600000
|time   V(typ)   V(min)   V(max)
0s        3.299V     2.699V     3.599V
1.001ns   3.311V     2.699V     3.294V
1.201ns   3.292V     2.7V       2.862V
1.702ns   2.985V     2.708V     880.3mV
2.302ns   1.705V     2.707V     487.4mV
2.703ns   916.7mV    2.664V     454.2mV
3.103ns   687.2mV    2.58V      436.5mV
5.255ns   532.3mV    1.126V     409.4mV
6.707ns   510.2mV    855.4mV    405.7mV
24.92ns   489.8mV    659.6mV    403.5mV
[Falling Waveform]
R_fixture= 50.000000
V_fixture= 0.0
V_fixture_min= 0.0
V_fixture_max= 0.0
|time   V(typ)   V(min)   V(max)
0s        2.761V     2.04V      3.13V
740.7ps   2.727V     2.04V      2.8V
920.9ps   2.659V     2.041V     2.236V
1.301ns   2.232V     2.041V     398.4mV
1.682ns   1.114V     1.973V     56.06mV
1.942ns   377.7mV    1.868V     9.089mV
2.182ns   135.5mV    1.724V     3.168mV
3.323ns   2.384mV    419.6mV    1.146mV
3.904ns   1.523mV    98.65mV    843.3uV
9.97ns    3.013uV    4.629uV    8.802uV
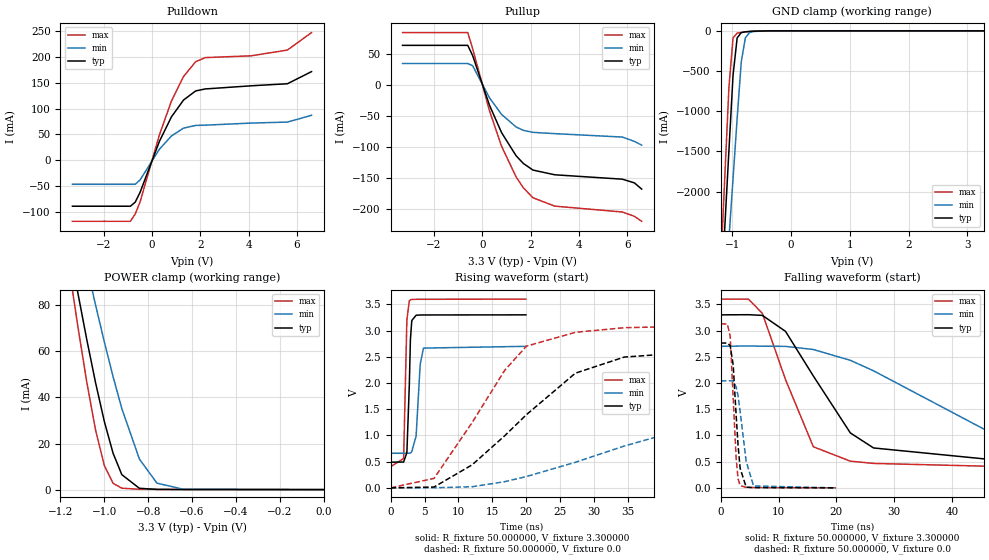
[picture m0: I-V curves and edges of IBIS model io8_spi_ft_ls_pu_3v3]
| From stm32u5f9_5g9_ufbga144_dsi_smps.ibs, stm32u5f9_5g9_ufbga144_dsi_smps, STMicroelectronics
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|   Model io8_spi_ft_ls_pu_3v3
[Model]  io8_spi_ft_ls_pu_3v3
Model_type I/O
Polarity   Non-Inverting
Enable   Active-Low
Vinl =   0.990000V
Vinh =   2.310000V
Vmeas =  1.650000V
Cref =   50.000000pF
Rref =   100.000000M
Vref =   0.0V
C_comp   3.495300pF   3.468500pF   3.534700pF
[Temperature Range]   25.000000   0.140000k   -40.000000
[Pullup Reference]   3.300000V   2.700000V   3.600000V
[Pulldown Reference]   0.0V   0.0V   0.0V
[POWER Clamp Reference]   3.300000V   2.700000V   3.600000V
[GND Clamp Reference]   0.0V   0.0V   0.0V
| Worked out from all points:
|   slope of the pulldown table from 0 to 0.495 V, typ, clamps not added: 8.73 ohm
|   slope of the pullup table from 0 to 0.495 V, typ, clamps not added: 9.64 ohm
|   GND clamp passes 1 mA (typ) near -0.50 V on its own axis
|   POWER clamp passes 1 mA (typ) near -0.85 V on its own axis
|   rising waveform, R_fixture 50.000000, V_fixture 3.300000: 20-80 % time 327ps typ, 506ps min, 283ps max; typ from 0.491 V to 3.3 V
|   rising waveform, R_fixture 50.000000, V_fixture 0.0: 20-80 % time 14.4ns typ, 31.3ns min, 9.35ns max; typ from 0.001 V to 2.76 V
|   falling waveform, R_fixture 50.000000, V_fixture 3.300000: 20-80 % time 9.55ns typ, 21.1ns min, 6.27ns max; typ from 3.3 V to 0.491 V
|   falling waveform, R_fixture 50.000000, V_fixture 0.0: 20-80 % time 951ps typ, 1.4ns min, 773ps max; typ from 2.76 V to 0.001 V
[Pulldown]
|Voltage   I(typ)   I(min)   I(max)
-3.3V     -89.71mA   -47.06mA   -119mA
-900mV    -89.71mA   -47.06mA   -119mA
-700mV    -81.75mA   -47.06mA   -104.8mA
-500mV    -62.92mA   -38.71mA   -81.44mA
300mV     36.2mA     21.01mA    48.7mA
800mV     84.06mA    46.96mA    114.8mA
1.3V      116.7mA    62.08mA    162.4mA
1.8V      134.4mA    67.38mA    191.2mA
2.2V      138.3mA    67.91mA    199.2mA
4.1V      144.4mA    71.94mA    202.7mA
5.6V      148.4mA    73.89mA    213.9mA
6.6V      172mA      87.1mA     247.9mA
[Pullup]
|Voltage   I(typ)   I(min)   I(max)
-3.3V     64.05mA    34.74mA    84.69mA
-600mV    64.05mA    34.74mA    84.69mA
-400mV    47.78mA    31.24mA    59.05mA
300mV     -32.62mA   -20.62mA   -41.63mA
800mV     -76.87mA   -47.45mA   -98.74mA
1.4V      -114.1mA   -67.68mA   -148.3mA
1.7V      -126.6mA   -73.14mA   -165.8mA
2.1V      -137.3mA   -76.42mA   -182mA
3V        -144.9mA   -78.48mA   -195.5mA
5.8V      -152mA     -84mA      -205mA
6.3V      -158mA     -91mA      -212mA
6.6V      -168mA     -97mA      -220mA
[GND_clamp]
|Voltage   I(typ)   I(min)   I(max)
-3.3V     -9.098A    -9.372A    -9.671A
-1.2V     -3.386A    -4.091A    -2.933A
-1.13V    -2.437A    -3.34A     -1.815A
-1.06V    -1.49A     -2.588A    -705.6mA
-990mV    -555.7mA   -1.839A    -89.03mA
-920mV    -88.12mA   -1.093A    -28.78mA
-850mV    -22.35mA   -387.4mA   -19.84mA
-780mV    -12.12mA   -88mA      -13.87mA
-710mV    -7.709mA   -22.52mA   -8.846mA
-640mV    -4.545mA   -7.864mA   -4.87mA
-360mV    -31.12uA   -173.5uA   -8.496uA
3.28V     0A         14.15nA    -7.901nA
[POWER_clamp]
|Voltage   I(typ)   I(min)   I(max)
-3.28V    1.355A     1.167A     1.665A
-1.16V    105.8mA    131.6mA    95.87mA
-1.12V    85.08mA    114mA      70.45mA
-1.08V    65.17mA    96.88mA    46.73mA
-1.04V    46.48mA    80.2mA     25.96mA
-1V       29.63mA    64.18mA    10.49mA
-960mV    15.81mA    49.06mA    2.743mA
-920mV    6.481mA    35.16mA    612.1uA
-840mV    577.5uA    13.29mA    137.7uA
-760mV    93.74uA    2.807mA    97.79uA
-640mV    40.06uA    158.9uA    59.34uA
0V        0A         19.33nA    0A
[Ramp]
| variable   typ   min   max
dV/dt_r  1.65687/14.39528n   1.22436/31.21616n   1.87825/9.32721n
dV/dt_f  1.68570/9.53410n   1.22374/21.03568n   1.91752/6.24401n
R_load = 50.000000
[Rising Waveform]
R_fixture= 50.000000
V_fixture= 3.300000
V_fixture_min= 2.700000
V_fixture_max= 3.600000
|time   V(typ)   V(min)   V(max)
0s        490.5mV    660.4mV    404.1mV
1.922ns   493.5mV    660.4mV    560.9mV
2.402ns   673.5mV    660mV      3.204V
2.763ns   1.967V     660.4mV    3.57V
2.923ns   2.831V     667.2mV    3.587V
3.123ns   3.191V     690.1mV    3.593V
3.764ns   3.293V     991.4mV    3.597V
4.364ns   3.297V     2.357V     3.597V
4.845ns   3.298V     2.666V     3.597V
19.94ns   3.3V       2.7V       3.6V
[Rising Waveform]
R_fixture= 50.000000
V_fixture= 0.0
V_fixture_min= 0.0
V_fixture_max= 0.0
|time   V(typ)   V(min)   V(max)
0s        557.7uV    595uV      578.3uV
6.406ns   16.31mV    2.131mV    181.6mV
12.01ns   439.1mV    21.85mV    1.245V
16.82ns   994.6mV    118.5mV    2.243V
20.02ns   1.397V     216.6mV    2.703V
27.23ns   2.188V     488.3mV    2.967V
34.43ns   2.495V     797.7mV    3.055V
58.46ns   2.714V     1.676V     3.122V
91.29ns   2.756V     1.952V     3.131V
398.8ns   2.762V     2.041V     3.131V
[Falling Waveform]
R_fixture= 50.000000
V_fixture= 3.300000
V_fixture_min= 2.700000
V_fixture_max= 3.600000
|time   V(typ)   V(min)   V(max)
0s        3.3V       2.7V       3.6V
4.805ns   3.303V     2.707V     3.599V
7.207ns   3.29V      2.702V     3.328V
11.21ns   2.985V     2.699V     2.065V
16.02ns   2.134V     2.639V     783.8mV
22.42ns   1.048V     2.433V     509.8mV
26.43ns   761.6mV    2.233V     466.8mV
46.45ns   543.7mV    1.067V     412mV
71.27ns   503.1mV    782.9mV    405.2mV
398.8ns   490.5mV    660.4mV    404.1mV
[Falling Waveform]
R_fixture= 50.000000
V_fixture= 0.0
V_fixture_min= 0.0
V_fixture_max= 0.0
|time   V(typ)   V(min)   V(max)
0s        2.762V     2.041V     3.131V
1.161ns   2.763V     2.041V     3.124V
1.642ns   2.712V     2.041V     2.889V
2.162ns   2.343V     2.042V     1.705V
2.683ns   1.364V     1.921V     549.4mV
3.003ns   812.7mV    1.752V     173mV
3.363ns   373.2mV    1.454V     43.54mV
4.404ns   13.6mV     506.8mV    8.448mV
5.686ns   5.161mV    36.55mV    7.211mV
19.94ns   557.7uV    595uV      578.3uV
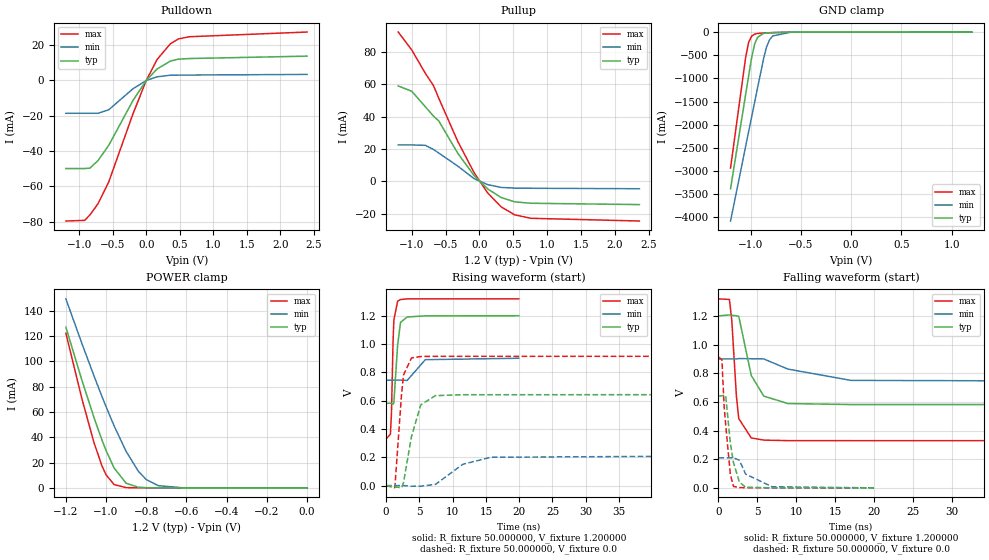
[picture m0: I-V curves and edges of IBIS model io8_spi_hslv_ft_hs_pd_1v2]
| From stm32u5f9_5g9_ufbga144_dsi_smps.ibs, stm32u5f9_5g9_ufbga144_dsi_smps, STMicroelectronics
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|   Model io8_spi_hslv_ft_hs_pd_1v2
[Model]  io8_spi_hslv_ft_hs_pd_1v2
Model_type I/O
Polarity   Non-Inverting
Enable   Active-Low
Vinl =   0.360000V
Vinh =   0.840000V
Vmeas =  0.600000V
Cref =   50.000000pF
Rref =   100.000000M
Vref =   0.0V
C_comp   3.133100pF   3.070300pF   3.178200pF
[Temperature Range]   25.000000   0.140000k   -40.000000
[Pullup Reference]   1.200000V   0.900000V   1.320000V
[Pulldown Reference]   0.0V   0.0V   0.0V
[POWER Clamp Reference]   1.200000V   0.900000V   1.320000V
[GND Clamp Reference]   0.0V   0.0V   0.0V
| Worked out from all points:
|   slope of the pulldown table from 0 to 0.18 V, typ, clamps not added: 25.4 ohm
|   slope of the pullup table from 0 to 0.18 V, typ, clamps not added: 27.8 ohm
|   GND clamp passes 1 mA (typ) near -0.51 V on its own axis
|   POWER clamp passes 1 mA (typ) near -0.86 V on its own axis
|   rising waveform, R_fixture 50.000000, V_fixture 1.200000: 20-80 % time 503ps typ, 1.14ns min, 303ps max; typ from 0.581 V to 1.2 V
|   rising waveform, R_fixture 50.000000, V_fixture 0.0: 20-80 % time 1.63ns typ, 3.83ns min, 812ps max; typ from 0 V to 0.642 V
|   falling waveform, R_fixture 50.000000, V_fixture 1.200000: 20-80 % time 1.65ns typ, 3.75ns min, 724ps max; typ from 1.2 V to 0.581 V
|   falling waveform, R_fixture 50.000000, V_fixture 0.0: 20-80 % time 995ps typ, 1.69ns min, 750ps max; typ from 0.642 V to 0 V
[Pulldown]
|Voltage   I(typ)   I(min)   I(max)
-1.2V     -49.85mA   -18.57mA   -79.56mA
-920mV    -49.85mA   -18.57mA   -79.19mA
-840mV    -49.59mA   -18.57mA   -76.08mA
-720mV    -45.32mA   -18.57mA   -69.74mA
-560mV    -36.71mA   -16.58mA   -57.44mA
-200mV    -11.43mA   -4.74mA    -19.03mA
0V        -10fA      -500fA     0A
160mV     6.476mA    2.075mA    11.78mA
360mV     10.99mA    2.989mA    20.81mA
480mV     12.07mA    3.053mA    23.52mA
640mV     12.42mA    3.074mA    24.76mA
2.4V      13.78mA    3.433mA    27.43mA
[Pullup]
|Voltage   I(typ)   I(min)   I(max)
-1.2V     59.08mA    22.59mA    92.41mA
-1V       55.78mA    22.59mA    81.32mA
-800mV    46.23mA    22.35mA    66.89mA
-680mV    40.46mA    19.81mA    59.32mA
-600mV    37.35mA    17.55mA    51.35mA
-320mV    17.39mA    9.466mA    24.7mA
-80mV     3.667mA    1.75mA     5.47mA
120mV     -4.592mA   -1.936mA   -7.077mA
320mV     -9.941mA   -3.694mA   -15.72mA
520mV     -12.61mA   -4.111mA   -20.65mA
760mV     -13.48mA   -4.204mA   -22.78mA
2.36V     -14.3mA    -4.5mA     -24.46mA
[GND_clamp]
|Voltage   I(typ)   I(min)   I(max)
-1.2V     -3.379A    -4.076A    -2.932A
-1.05V    -1.35A     -2.47A     -550.7mA
-1.02V    -947.8mA   -2.15A     -221.5mA
-990mV    -552.4mA   -1.829A    -88.45mA
-960mV    -255.3mA   -1.51A     -44.89mA
-930mV    -111.8mA   -1.191A    -30.69mA
-870mV    -28.36mA   -564.6mA   -21.36mA
-840mV    -18.66mA   -309.5mA   -18.51mA
-810mV    -14.08mA   -161.6mA   -15.94mA
-780mV    -11.38mA   -83.33mA   -13.55mA
-600mV    -3.019mA   -4.329mA   -3.104mA
1.2V      30.28uA    18.17uA    37.27uA
[POWER_clamp]
|Voltage   I(typ)   I(min)   I(max)
-1.2V     127mA      149.4mA    122.2mA
-1.12V    84.97mA    114mA      70.27mA
-1.06V    55.51mA    88.42mA    35.67mA
-1.02V    37.63mA    72.04mA    17.17mA
-1V       29.51mA    64.13mA    10.3mA
-960mV    15.69mA    48.99mA    2.571mA
-900mV    3.624mA    28.77mA    182.8uA
-840mV    490.7uA    13.24mA    11.35uA
-800mV    116.8uA    6.532mA    1.77uA
-740mV    13.2uA     1.723mA    109.1nA
-620mV    167.4nA    79.36uA    0A
0V        0A         17.87nA    0A
[Ramp]
| variable   typ   min   max
dV/dt_r  0.38526/1.62847n   0.12542/3.82631n   0.54788/0.80683n
dV/dt_f  0.37090/1.64319n   92.62200m/3.75257n  0.59417/0.72001n
R_load = 50.000000
[Rising Waveform]
R_fixture= 50.000000
V_fixture= 1.200000
V_fixture_min= 0.900000
V_fixture_max= 1.320000
|time   V(typ)   V(min)   V(max)
0s        581.4mV    745.2mV    329.3mV
640.6ps   581.7mV    745.2mV    363mV
800.8ps   580.5mV    745.2mV    515.1mV
1.041ns   574.6mV    745.2mV    1.025V
1.161ns   588.3mV    745.2mV    1.17V
1.722ns   992mV      745.3mV    1.303V
2.162ns   1.153V     745.3mV    1.314V
3.163ns   1.191V     742.9mV    1.319V
5.886ns   1.199V     889.5mV    1.319V
19.94ns   1.2V       899.5mV    1.319V
[Rising Waveform]
R_fixture= 50.000000
V_fixture= 0.0
V_fixture_min= 0.0
V_fixture_max= 0.0
|time   V(typ)   V(min)   V(max)
0s        -2.996uV   836.7nV    -21.61uV
1.301ns   -8.519mV   -7.398uV   -14.9mV
2.302ns   -15.9mV    34.84uV    636.8mV
2.603ns   18.65mV    136.9uV    780.9mV
3.804ns   345.8mV    -4.868mV   901.6mV
5.205ns   570.7mV    -4.054mV   912mV
7.407ns   635.4mV    8.285mV    913mV
11.51ns   641.9mV    150.1mV    913.2mV
15.72ns   642.1mV    200mV      913.2mV
49.85ns   642.2mV    209.1mV    913.2mV
[Falling Waveform]
R_fixture= 50.000000
V_fixture= 1.200000
V_fixture_min= 0.900000
V_fixture_max= 1.320000
|time   V(typ)   V(min)   V(max)
0s        1.2V       899.5mV    1.319V
1.401ns   1.207V     899.5mV    1.315V
1.702ns   1.204V     899.5mV    1.173V
2.302ns   1.201V     899.4mV    638mV
2.603ns   1.197V     902.2mV    483.3mV
4.204ns   784.6mV    901.1mV    348.5mV
5.806ns   640.5mV    899.8mV    333.1mV
8.909ns   588.4mV    828.9mV    329.5mV
17.02ns   581.4mV    749.9mV    329.3mV
49.85ns   581.4mV    745.2mV    329.3mV
[Falling Waveform]
R_fixture= 50.000000
V_fixture= 0.0
V_fixture_min= 0.0
V_fixture_max= 0.0
|time   V(typ)   V(min)   V(max)
0s        642.2mV    209.1mV    913.2mV
440.4ps   642mV      209.1mV    894.8mV
720.7ps   646.7mV    209.1mV    571.5mV
920.9ps   644.3mV    209.2mV    442.6mV
1.522ns   312.3mV    209mV      93.57mV
1.922ns   176.5mV    210.1mV    10.2mV
2.683ns   39.76mV    193.1mV    2.053mV
3.483ns   4.278mV    95.8mV     710.3uV
6.887ns   222.7uV    7.362mV    -4.269uV
19.94ns   -2.996uV   836.7nV    -21.61uV
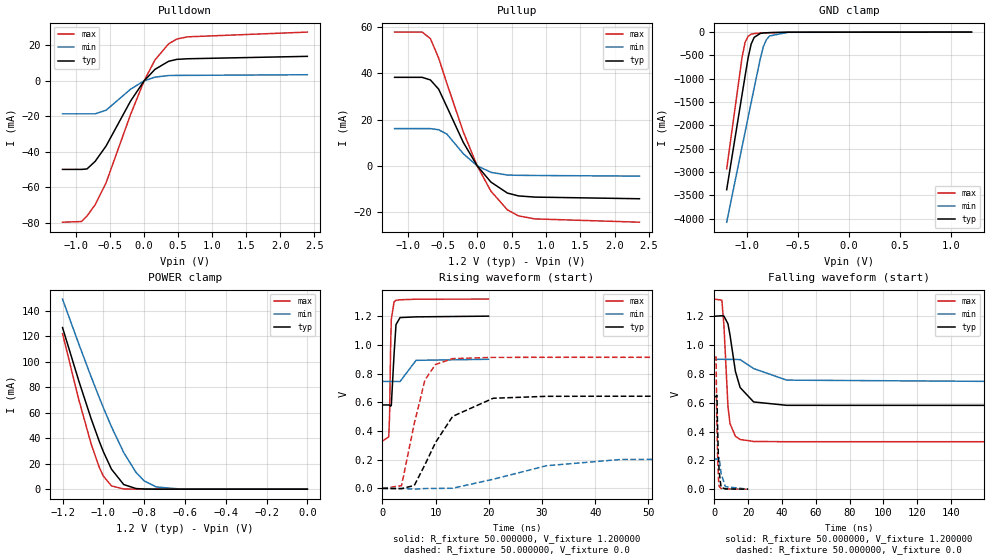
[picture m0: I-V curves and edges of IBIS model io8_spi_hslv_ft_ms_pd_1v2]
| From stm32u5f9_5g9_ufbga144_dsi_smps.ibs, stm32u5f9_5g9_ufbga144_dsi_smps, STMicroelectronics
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|   Model io8_spi_hslv_ft_ms_pd_1v2
[Model]  io8_spi_hslv_ft_ms_pd_1v2
Model_type I/O
Polarity   Non-Inverting
Enable   Active-Low
Vinl =   0.360000V
Vinh =   0.840000V
Vmeas =  0.600000V
Cref =   50.000000pF
Rref =   100.000000M
Vref =   0.0V
C_comp   3.133100pF   3.070300pF   3.178200pF
[Temperature Range]   25.000000   0.140000k   -40.000000
[Pullup Reference]   1.200000V   0.900000V   1.320000V
[Pulldown Reference]   0.0V   0.0V   0.0V
[POWER Clamp Reference]   1.200000V   0.900000V   1.320000V
[GND Clamp Reference]   0.0V   0.0V   0.0V
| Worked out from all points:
|   slope of the pulldown table from 0 to 0.18 V, typ, clamps not added: 25.4 ohm
|   slope of the pullup table from 0 to 0.18 V, typ, clamps not added: 27.8 ohm
|   GND clamp passes 1 mA (typ) near -0.51 V on its own axis
|   POWER clamp passes 1 mA (typ) near -0.86 V on its own axis
|   rising waveform, R_fixture 50.000000, V_fixture 1.200000: 20-80 % time 441ps typ, 1.03ns min, 262ps max; typ from 0.581 V to 1.2 V
|   rising waveform, R_fixture 50.000000, V_fixture 0.0: 20-80 % time 5.96ns typ, 13.8ns min, 3.13ns max; typ from 0 V to 0.642 V
|   falling waveform, R_fixture 50.000000, V_fixture 1.200000: 20-80 % time 6.09ns typ, 13.2ns min, 2.67ns max; typ from 1.2 V to 0.581 V
|   falling waveform, R_fixture 50.000000, V_fixture 0.0: 20-80 % time 1.05ns typ, 1.77ns min, 826ps max; typ from 0.642 V to 0 V
[Pulldown]
|Voltage   I(typ)   I(min)   I(max)
-1.2V     -49.85mA   -18.57mA   -79.56mA
-920mV    -49.85mA   -18.57mA   -79.19mA
-840mV    -49.59mA   -18.57mA   -76.08mA
-720mV    -45.32mA   -18.57mA   -69.74mA
-560mV    -36.71mA   -16.58mA   -57.44mA
-200mV    -11.43mA   -4.739mA   -19.03mA
0V        -10fA      -500fA     0A
160mV     6.476mA    2.075mA    11.78mA
360mV     10.99mA    2.989mA    20.81mA
480mV     12.07mA    3.053mA    23.52mA
640mV     12.42mA    3.074mA    24.76mA
2.4V      13.78mA    3.432mA    27.43mA
[Pullup]
|Voltage   I(typ)   I(min)   I(max)
-1.2V     38.3mA     16.09mA    57.9mA
-800mV    38.3mA     16.09mA    57.9mA
-680mV    37.18mA    16.09mA    55.12mA
-560mV    33.2mA     15.59mA    46.68mA
-440mV    25.53mA    13.72mA    35.67mA
-200mV    10.05mA    5.175mA    14.59mA
0V        0A         0A         0A
200mV     -7.072mA   -2.851mA   -11mA
440mV     -11.84mA   -4.03mA    -19.1mA
600mV     -13.07mA   -4.154mA   -21.71mA
840mV     -13.59mA   -4.223mA   -23.04mA
2.36V     -14.3mA    -4.5mA     -24.46mA
[GND_clamp]
|Voltage   I(typ)   I(min)   I(max)
-1.2V     -3.379A    -4.076A    -2.932A
-1.05V    -1.35A     -2.47A     -550.7mA
-1.02V    -947.8mA   -2.15A     -221.5mA
-990mV    -552.4mA   -1.829A    -88.45mA
-960mV    -255.3mA   -1.51A     -44.89mA
-930mV    -111.8mA   -1.191A    -30.69mA
-870mV    -28.36mA   -564.6mA   -21.36mA
-840mV    -18.66mA   -309.5mA   -18.51mA
-810mV    -14.08mA   -161.6mA   -15.94mA
-780mV    -11.38mA   -83.33mA   -13.55mA
-600mV    -3.019mA   -4.329mA   -3.104mA
1.2V      30.28uA    18.17uA    37.27uA
[POWER_clamp]
|Voltage   I(typ)   I(min)   I(max)
-1.2V     127mA      149.4mA    122.2mA
-1.12V    84.97mA    114mA      70.27mA
-1.06V    55.51mA    88.42mA    35.67mA
-1.02V    37.63mA    72.04mA    17.17mA
-1V       29.51mA    64.13mA    10.3mA
-960mV    15.69mA    48.99mA    2.571mA
-900mV    3.624mA    28.77mA    182.8uA
-840mV    490.7uA    13.24mA    11.35uA
-800mV    116.8uA    6.532mA    1.77uA
-740mV    13.2uA     1.723mA    109.1nA
-620mV    167.4nA    79.36uA    0A
0V        0A         17.87nA    0A
[Ramp]
| variable   typ   min   max
dV/dt_r  0.38527/5.95202n   0.12539/13.77971n   0.54788/3.11308n
dV/dt_f  0.37089/6.08157n   92.62200m/13.16507n 0.59417/2.66376n
R_load = 50.000000
[Rising Waveform]
R_fixture= 50.000000
V_fixture= 1.200000
V_fixture_min= 0.900000
V_fixture_max= 1.320000
|time   V(typ)   V(min)   V(max)
0s        581.3mV    745.2mV    329.2mV
1.201ns   581.4mV    745.2mV    359.3mV
1.361ns   579.5mV    745.2mV    510.4mV
1.562ns   573.3mV    745.2mV    1.005V
1.682ns   578.7mV    745.2mV    1.177V
2.202ns   936.4mV    745.2mV    1.3V
2.563ns   1.141V     745.3mV    1.31V
3.323ns   1.19V      744.1mV    1.314V
6.326ns   1.195V     892.2mV    1.318V
19.94ns   1.2V       899.5mV    1.319V
[Rising Waveform]
R_fixture= 50.000000
V_fixture= 0.0
V_fixture_min= 0.0
V_fixture_max= 0.0
|time   V(typ)   V(min)   V(max)
0s        1.941nV    235.2nV    1.147nV
3.604ns   -2.098mV   -33.55uV   18.99mV
6.006ns   20.74mV    -5.303mV   453.3mV
8.008ns   165.7mV    -724.3uV   756.3mV
10.01ns   321mV      -289.7uV   863.8mV
13.21ns   501.8mV    1.106mV    904.2mV
20.82ns   628mV      63.81mV    912.8mV
30.83ns   641.5mV    158mV      913.1mV
44.84ns   642.1mV    201.7mV    913.1mV
199.4ns   642.1mV    209.1mV    913.1mV
[Falling Waveform]
R_fixture= 50.000000
V_fixture= 1.200000
V_fixture_min= 0.900000
V_fixture_max= 1.320000
|time   V(typ)   V(min)   V(max)
0s        1.2V       899.5mV    1.319V
4.404ns   1.203V     901.4mV    1.311V
5.606ns   1.201V     900.4mV    1.139V
8.008ns   1.147V     900.3mV    574.5mV
9.209ns   1.07V      900.3mV    455.6mV
12.41ns   817.6mV    900mV      366.6mV
15.22ns   704.9mV    899mV      344.8mV
23.22ns   605.1mV    836.8mV    331mV
42.84ns   581.7mV    756.5mV    329.2mV
199.4ns   581.3mV    745.2mV    329.2mV
[Falling Waveform]
R_fixture= 50.000000
V_fixture= 0.0
V_fixture_min= 0.0
V_fixture_max= 0.0
|time   V(typ)   V(min)   V(max)
0s        642.1mV    209.1mV    913.1mV
961ps     642.2mV    209.1mV    917.4mV
1.321ns   651.8mV    209.2mV    546.7mV
1.481ns   651mV      209.2mV    449.9mV
1.802ns   456.9mV    209.2mV    260.2mV
2.322ns   231.8mV    209.1mV    81.19mV
2.803ns   121.9mV    216.5mV    18.99mV
3.924ns   12.89mV    109.9mV    4.925mV
6.446ns   1.913mV    17.54mV    1.146mV
19.94ns   1.941nV    235.2nV    1.147nV
